VERSION 5.7 ;
BUSBITCHARS "[]" ;
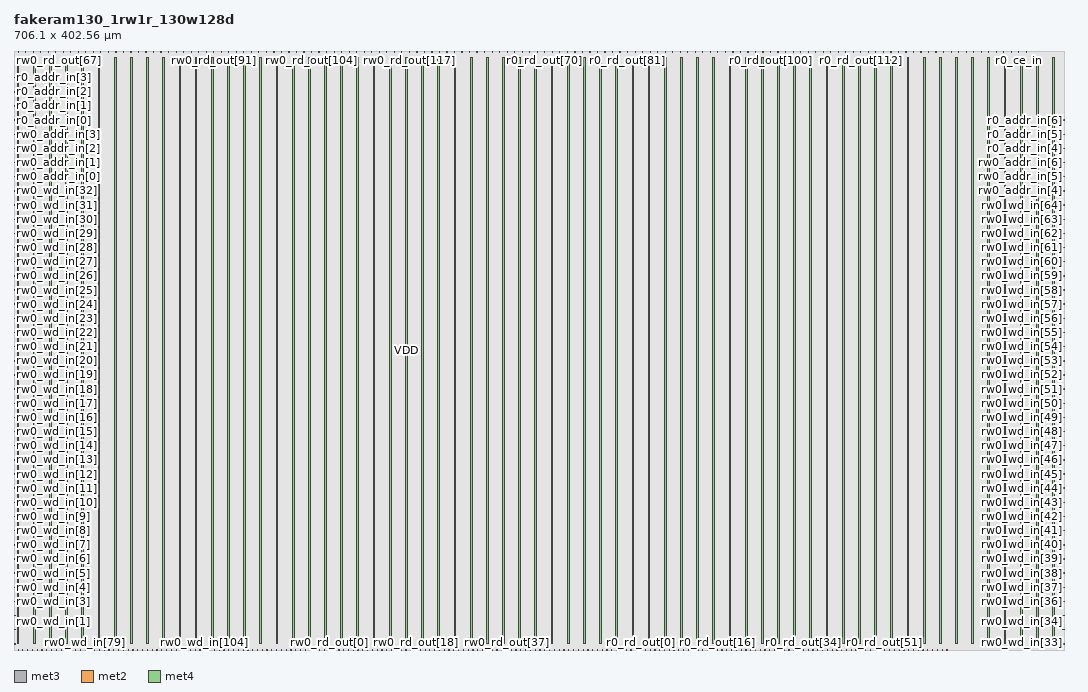
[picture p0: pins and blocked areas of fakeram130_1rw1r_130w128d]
MACRO fakeram130_1rw1r_130w128d
  FOREIGN fakeram130_1rw1r_130w128d 0 0 ;
  SYMMETRY X Y R90 ;
  SIZE 706.100 BY 402.560 ;
  CLASS BLOCK ;
  PIN rw0_wd_in[0]
    DIRECTION INPUT ;
    USE SIGNAL ;
    SHAPE ABUTMENT ;
    PORT
      LAYER met3 ;
      RECT 0.000 3.930 0.900 4.230 ;
    END
  END rw0_wd_in[0]
  PIN rw0_wd_in[1]
    DIRECTION INPUT ;
    USE SIGNAL ;
    SHAPE ABUTMENT ;
    PORT
      LAYER met3 ;
      RECT 0.000 13.450 0.900 13.750 ;
    END
  END rw0_wd_in[1]
  PIN rw0_wd_in[2]
    DIRECTION INPUT ;
    USE SIGNAL ;
    SHAPE ABUTMENT ;
    PORT
      LAYER met3 ;
      RECT 0.000 22.970 0.900 23.270 ;
    END
  END rw0_wd_in[2]
  PIN rw0_wd_in[3]
    DIRECTION INPUT ;
    USE SIGNAL ;
    SHAPE ABUTMENT ;
    PORT
      LAYER met3 ;
      RECT 0.000 32.490 0.900 32.790 ;
    END
  END rw0_wd_in[3]
  PIN rw0_wd_in[4]
    DIRECTION INPUT ;
    USE SIGNAL ;
    SHAPE ABUTMENT ;
    PORT
      LAYER met3 ;
      RECT 0.000 42.010 0.900 42.310 ;
    END
  END rw0_wd_in[4]
  PIN rw0_wd_in[5]
    DIRECTION INPUT ;
    USE SIGNAL ;
    SHAPE ABUTMENT ;
    PORT
      LAYER met3 ;
      RECT 0.000 51.530 0.900 51.830 ;
    END
  END rw0_wd_in[5]
  PIN rw0_wd_in[6]
    DIRECTION INPUT ;
    USE SIGNAL ;
    SHAPE ABUTMENT ;
    PORT
      LAYER met3 ;
      RECT 0.000 61.050 0.900 61.350 ;
    END
  END rw0_wd_in[6]
  PIN rw0_wd_in[7]
    DIRECTION INPUT ;
    USE SIGNAL ;
    SHAPE ABUTMENT ;
    PORT
      LAYER met3 ;
      RECT 0.000 70.570 0.900 70.870 ;
    END
  END rw0_wd_in[7]
  PIN rw0_wd_in[8]
    DIRECTION INPUT ;
    USE SIGNAL ;
    SHAPE ABUTMENT ;
    PORT
      LAYER met3 ;
      RECT 0.000 80.090 0.900 80.390 ;
    END
  END rw0_wd_in[8]
  PIN rw0_wd_in[9]
    DIRECTION INPUT ;
    USE SIGNAL ;
    SHAPE ABUTMENT ;
    PORT
      LAYER met3 ;
      RECT 0.000 89.610 0.900 89.910 ;
    END
  END rw0_wd_in[9]
  PIN rw0_wd_in[10]
    DIRECTION INPUT ;
    USE SIGNAL ;
    SHAPE ABUTMENT ;
    PORT
      LAYER met3 ;
      RECT 0.000 99.130 0.900 99.430 ;
    END
  END rw0_wd_in[10]
  PIN rw0_wd_in[11]
    DIRECTION INPUT ;
    USE SIGNAL ;
    SHAPE ABUTMENT ;
    PORT
      LAYER met3 ;
      RECT 0.000 108.650 0.900 108.950 ;
    END
  END rw0_wd_in[11]
  PIN rw0_wd_in[12]
    DIRECTION INPUT ;
    USE SIGNAL ;
    SHAPE ABUTMENT ;
    PORT
      LAYER met3 ;
      RECT 0.000 118.170 0.900 118.470 ;
    END
  END rw0_wd_in[12]
  PIN rw0_wd_in[13]
    DIRECTION INPUT ;
    USE SIGNAL ;
    SHAPE ABUTMENT ;
    PORT
      LAYER met3 ;
      RECT 0.000 127.690 0.900 127.990 ;
    END
  END rw0_wd_in[13]
  PIN rw0_wd_in[14]
    DIRECTION INPUT ;
    USE SIGNAL ;
    SHAPE ABUTMENT ;
    PORT
      LAYER met3 ;
      RECT 0.000 137.210 0.900 137.510 ;
    END
  END rw0_wd_in[14]
  PIN rw0_wd_in[15]
    DIRECTION INPUT ;
    USE SIGNAL ;
    SHAPE ABUTMENT ;
    PORT
      LAYER met3 ;
      RECT 0.000 146.730 0.900 147.030 ;
    END
  END rw0_wd_in[15]
  PIN rw0_wd_in[16]
    DIRECTION INPUT ;
    USE SIGNAL ;
    SHAPE ABUTMENT ;
    PORT
      LAYER met3 ;
      RECT 0.000 156.250 0.900 156.550 ;
    END
  END rw0_wd_in[16]
  PIN rw0_wd_in[17]
    DIRECTION INPUT ;
    USE SIGNAL ;
    SHAPE ABUTMENT ;
    PORT
      LAYER met3 ;
      RECT 0.000 165.770 0.900 166.070 ;
    END
  END rw0_wd_in[17]
  PIN rw0_wd_in[18]
    DIRECTION INPUT ;
    USE SIGNAL ;
    SHAPE ABUTMENT ;
    PORT
      LAYER met3 ;
      RECT 0.000 175.290 0.900 175.590 ;
    END
  END rw0_wd_in[18]
  PIN rw0_wd_in[19]
    DIRECTION INPUT ;
    USE SIGNAL ;
    SHAPE ABUTMENT ;
    PORT
      LAYER met3 ;
      RECT 0.000 184.810 0.900 185.110 ;
    END
  END rw0_wd_in[19]
  PIN rw0_wd_in[20]
    DIRECTION INPUT ;
    USE SIGNAL ;
    SHAPE ABUTMENT ;
    PORT
      LAYER met3 ;
      RECT 0.000 194.330 0.900 194.630 ;
    END
  END rw0_wd_in[20]
  PIN rw0_wd_in[21]
    DIRECTION INPUT ;
    USE SIGNAL ;
    SHAPE ABUTMENT ;
    PORT
      LAYER met3 ;
      RECT 0.000 203.850 0.900 204.150 ;
    END
  END rw0_wd_in[21]
  PIN rw0_wd_in[22]
    DIRECTION INPUT ;
    USE SIGNAL ;
    SHAPE ABUTMENT ;
    PORT
      LAYER met3 ;
      RECT 0.000 213.370 0.900 213.670 ;
    END
  END rw0_wd_in[22]
  PIN rw0_wd_in[23]
    DIRECTION INPUT ;
    USE SIGNAL ;
    SHAPE ABUTMENT ;
    PORT
      LAYER met3 ;
      RECT 0.000 222.890 0.900 223.190 ;
    END
  END rw0_wd_in[23]
  PIN rw0_wd_in[24]
    DIRECTION INPUT ;
    USE SIGNAL ;
    SHAPE ABUTMENT ;
    PORT
      LAYER met3 ;
      RECT 0.000 232.410 0.900 232.710 ;
    END
  END rw0_wd_in[24]
  PIN rw0_wd_in[25]
    DIRECTION INPUT ;
    USE SIGNAL ;
    SHAPE ABUTMENT ;
    PORT
      LAYER met3 ;
      RECT 0.000 241.930 0.900 242.230 ;
    END
  END rw0_wd_in[25]
  PIN rw0_wd_in[26]
    DIRECTION INPUT ;
    USE SIGNAL ;
    SHAPE ABUTMENT ;
    PORT
      LAYER met3 ;
      RECT 0.000 251.450 0.900 251.750 ;
    END
  END rw0_wd_in[26]
  PIN rw0_wd_in[27]
    DIRECTION INPUT ;
    USE SIGNAL ;
    SHAPE ABUTMENT ;
    PORT
      LAYER met3 ;
      RECT 0.000 260.970 0.900 261.270 ;
    END
  END rw0_wd_in[27]
  PIN rw0_wd_in[28]
    DIRECTION INPUT ;
    USE SIGNAL ;
    SHAPE ABUTMENT ;
    PORT
      LAYER met3 ;
      RECT 0.000 270.490 0.900 270.790 ;
    END
  END rw0_wd_in[28]
  PIN rw0_wd_in[29]
    DIRECTION INPUT ;
    USE SIGNAL ;
    SHAPE ABUTMENT ;
    PORT
      LAYER met3 ;
      RECT 0.000 280.010 0.900 280.310 ;
    END
  END rw0_wd_in[29]
  PIN rw0_wd_in[30]
    DIRECTION INPUT ;
    USE SIGNAL ;
    SHAPE ABUTMENT ;
    PORT
      LAYER met3 ;
      RECT 0.000 289.530 0.900 289.830 ;
    END
  END rw0_wd_in[30]
  PIN rw0_wd_in[31]
    DIRECTION INPUT ;
    USE SIGNAL ;
    SHAPE ABUTMENT ;
    PORT
      LAYER met3 ;
      RECT 0.000 299.050 0.900 299.350 ;
    END
  END rw0_wd_in[31]
  PIN rw0_wd_in[32]
    DIRECTION INPUT ;
    USE SIGNAL ;
    SHAPE ABUTMENT ;
    PORT
      LAYER met3 ;
      RECT 0.000 308.570 0.900 308.870 ;
    END
  END rw0_wd_in[32]
  PIN rw0_wd_in[33]
    DIRECTION INPUT ;
    USE SIGNAL ;
    SHAPE ABUTMENT ;
    PORT
      LAYER met3 ;
      RECT 705.200 3.930 706.100 4.230 ;
    END
  END rw0_wd_in[33]
  PIN rw0_wd_in[34]
    DIRECTION INPUT ;
    USE SIGNAL ;
    SHAPE ABUTMENT ;
    PORT
      LAYER met3 ;
      RECT 705.200 13.450 706.100 13.750 ;
    END
  END rw0_wd_in[34]
  PIN rw0_wd_in[35]
    DIRECTION INPUT ;
    USE SIGNAL ;
    SHAPE ABUTMENT ;
    PORT
      LAYER met3 ;
      RECT 705.200 22.970 706.100 23.270 ;
    END
  END rw0_wd_in[35]
  PIN rw0_wd_in[36]
    DIRECTION INPUT ;
    USE SIGNAL ;
    SHAPE ABUTMENT ;
    PORT
      LAYER met3 ;
      RECT 705.200 32.490 706.100 32.790 ;
    END
  END rw0_wd_in[36]
  PIN rw0_wd_in[37]
    DIRECTION INPUT ;
    USE SIGNAL ;
    SHAPE ABUTMENT ;
    PORT
      LAYER met3 ;
      RECT 705.200 42.010 706.100 42.310 ;
    END
  END rw0_wd_in[37]
  PIN rw0_wd_in[38]
    DIRECTION INPUT ;
    USE SIGNAL ;
    SHAPE ABUTMENT ;
    PORT
      LAYER met3 ;
      RECT 705.200 51.530 706.100 51.830 ;
    END
  END rw0_wd_in[38]
  PIN rw0_wd_in[39]
    DIRECTION INPUT ;
    USE SIGNAL ;
    SHAPE ABUTMENT ;
    PORT
      LAYER met3 ;
      RECT 705.200 61.050 706.100 61.350 ;
    END
  END rw0_wd_in[39]
  PIN rw0_wd_in[40]
    DIRECTION INPUT ;
    USE SIGNAL ;
    SHAPE ABUTMENT ;
    PORT
      LAYER met3 ;
      RECT 705.200 70.570 706.100 70.870 ;
    END
  END rw0_wd_in[40]
  PIN rw0_wd_in[41]
    DIRECTION INPUT ;
    USE SIGNAL ;
    SHAPE ABUTMENT ;
    PORT
      LAYER met3 ;
      RECT 705.200 80.090 706.100 80.390 ;
    END
  END rw0_wd_in[41]
  PIN rw0_wd_in[42]
    DIRECTION INPUT ;
    USE SIGNAL ;
    SHAPE ABUTMENT ;
    PORT
      LAYER met3 ;
      RECT 705.200 89.610 706.100 89.910 ;
    END
  END rw0_wd_in[42]
  PIN rw0_wd_in[43]
    DIRECTION INPUT ;
    USE SIGNAL ;
    SHAPE ABUTMENT ;
    PORT
      LAYER met3 ;
      RECT 705.200 99.130 706.100 99.430 ;
    END
  END rw0_wd_in[43]
  PIN rw0_wd_in[44]
    DIRECTION INPUT ;
    USE SIGNAL ;
    SHAPE ABUTMENT ;
    PORT
      LAYER met3 ;
      RECT 705.200 108.650 706.100 108.950 ;
    END
  END rw0_wd_in[44]
  PIN rw0_wd_in[45]
    DIRECTION INPUT ;
    USE SIGNAL ;
    SHAPE ABUTMENT ;
    PORT
      LAYER met3 ;
      RECT 705.200 118.170 706.100 118.470 ;
    END
  END rw0_wd_in[45]
  PIN rw0_wd_in[46]
    DIRECTION INPUT ;
    USE SIGNAL ;
    SHAPE ABUTMENT ;
    PORT
      LAYER met3 ;
      RECT 705.200 127.690 706.100 127.990 ;
    END
  END rw0_wd_in[46]
  PIN rw0_wd_in[47]
    DIRECTION INPUT ;
    USE SIGNAL ;
    SHAPE ABUTMENT ;
    PORT
      LAYER met3 ;
      RECT 705.200 137.210 706.100 137.510 ;
    END
  END rw0_wd_in[47]
  PIN rw0_wd_in[48]
    DIRECTION INPUT ;
    USE SIGNAL ;
    SHAPE ABUTMENT ;
    PORT
      LAYER met3 ;
      RECT 705.200 146.730 706.100 147.030 ;
    END
  END rw0_wd_in[48]
  PIN rw0_wd_in[49]
    DIRECTION INPUT ;
    USE SIGNAL ;
    SHAPE ABUTMENT ;
    PORT
      LAYER met3 ;
      RECT 705.200 156.250 706.100 156.550 ;
    END
  END rw0_wd_in[49]
  PIN rw0_wd_in[50]
    DIRECTION INPUT ;
    USE SIGNAL ;
    SHAPE ABUTMENT ;
    PORT
      LAYER met3 ;
      RECT 705.200 165.770 706.100 166.070 ;
    END
  END rw0_wd_in[50]
  PIN rw0_wd_in[51]
    DIRECTION INPUT ;
    USE SIGNAL ;
    SHAPE ABUTMENT ;
    PORT
      LAYER met3 ;
      RECT 705.200 175.290 706.100 175.590 ;
    END
  END rw0_wd_in[51]
  PIN rw0_wd_in[52]
    DIRECTION INPUT ;
    USE SIGNAL ;
    SHAPE ABUTMENT ;
    PORT
      LAYER met3 ;
      RECT 705.200 184.810 706.100 185.110 ;
    END
  END rw0_wd_in[52]
  PIN rw0_wd_in[53]
    DIRECTION INPUT ;
    USE SIGNAL ;
    SHAPE ABUTMENT ;
    PORT
      LAYER met3 ;
      RECT 705.200 194.330 706.100 194.630 ;
    END
  END rw0_wd_in[53]
  PIN rw0_wd_in[54]
    DIRECTION INPUT ;
    USE SIGNAL ;
    SHAPE ABUTMENT ;
    PORT
      LAYER met3 ;
      RECT 705.200 203.850 706.100 204.150 ;
    END
  END rw0_wd_in[54]
  PIN rw0_wd_in[55]
    DIRECTION INPUT ;
    USE SIGNAL ;
    SHAPE ABUTMENT ;
    PORT
      LAYER met3 ;
      RECT 705.200 213.370 706.100 213.670 ;
    END
  END rw0_wd_in[55]
  PIN rw0_wd_in[56]
    DIRECTION INPUT ;
    USE SIGNAL ;
    SHAPE ABUTMENT ;
    PORT
      LAYER met3 ;
      RECT 705.200 222.890 706.100 223.190 ;
    END
  END rw0_wd_in[56]
  PIN rw0_wd_in[57]
    DIRECTION INPUT ;
    USE SIGNAL ;
    SHAPE ABUTMENT ;
    PORT
      LAYER met3 ;
      RECT 705.200 232.410 706.100 232.710 ;
    END
  END rw0_wd_in[57]
  PIN rw0_wd_in[58]
    DIRECTION INPUT ;
    USE SIGNAL ;
    SHAPE ABUTMENT ;
    PORT
      LAYER met3 ;
      RECT 705.200 241.930 706.100 242.230 ;
    END
  END rw0_wd_in[58]
  PIN rw0_wd_in[59]
    DIRECTION INPUT ;
    USE SIGNAL ;
    SHAPE ABUTMENT ;
    PORT
      LAYER met3 ;
      RECT 705.200 251.450 706.100 251.750 ;
    END
  END rw0_wd_in[59]
  PIN rw0_wd_in[60]
    DIRECTION INPUT ;
    USE SIGNAL ;
    SHAPE ABUTMENT ;
    PORT
      LAYER met3 ;
      RECT 705.200 260.970 706.100 261.270 ;
    END
  END rw0_wd_in[60]
  PIN rw0_wd_in[61]
    DIRECTION INPUT ;
    USE SIGNAL ;
    SHAPE ABUTMENT ;
    PORT
      LAYER met3 ;
      RECT 705.200 270.490 706.100 270.790 ;
    END
  END rw0_wd_in[61]
  PIN rw0_wd_in[62]
    DIRECTION INPUT ;
    USE SIGNAL ;
    SHAPE ABUTMENT ;
    PORT
      LAYER met3 ;
      RECT 705.200 280.010 706.100 280.310 ;
    END
  END rw0_wd_in[62]
  PIN rw0_wd_in[63]
    DIRECTION INPUT ;
    USE SIGNAL ;
    SHAPE ABUTMENT ;
    PORT
      LAYER met3 ;
      RECT 705.200 289.530 706.100 289.830 ;
    END
  END rw0_wd_in[63]
  PIN rw0_wd_in[64]
    DIRECTION INPUT ;
    USE SIGNAL ;
    SHAPE ABUTMENT ;
    PORT
      LAYER met3 ;
      RECT 705.200 299.050 706.100 299.350 ;
    END
  END rw0_wd_in[64]
  PIN rw0_wd_in[65]
    DIRECTION OUTPUT ;
    USE SIGNAL ;
    SHAPE ABUTMENT ;
    PORT
      LAYER met2 ;
      RECT 2.690 0.000 2.830 0.420 ;
    END
  END rw0_wd_in[65]
  PIN rw0_wd_in[66]
    DIRECTION OUTPUT ;
    USE SIGNAL ;
    SHAPE ABUTMENT ;
    PORT
      LAYER met2 ;
      RECT 5.910 0.000 6.050 0.420 ;
    END
  END rw0_wd_in[66]
  PIN rw0_wd_in[67]
    DIRECTION OUTPUT ;
    USE SIGNAL ;
    SHAPE ABUTMENT ;
    PORT
      LAYER met2 ;
      RECT 9.130 0.000 9.270 0.420 ;
    END
  END rw0_wd_in[67]
  PIN rw0_wd_in[68]
    DIRECTION OUTPUT ;
    USE SIGNAL ;
    SHAPE ABUTMENT ;
    PORT
      LAYER met2 ;
      RECT 12.350 0.000 12.490 0.420 ;
    END
  END rw0_wd_in[68]
  PIN rw0_wd_in[69]
    DIRECTION OUTPUT ;
    USE SIGNAL ;
    SHAPE ABUTMENT ;
    PORT
      LAYER met2 ;
      RECT 15.570 0.000 15.710 0.420 ;
    END
  END rw0_wd_in[69]
  PIN rw0_wd_in[70]
    DIRECTION OUTPUT ;
    USE SIGNAL ;
    SHAPE ABUTMENT ;
    PORT
      LAYER met2 ;
      RECT 18.790 0.000 18.930 0.420 ;
    END
  END rw0_wd_in[70]
  PIN rw0_wd_in[71]
    DIRECTION OUTPUT ;
    USE SIGNAL ;
    SHAPE ABUTMENT ;
    PORT
      LAYER met2 ;
      RECT 22.010 0.000 22.150 0.420 ;
    END
  END rw0_wd_in[71]
  PIN rw0_wd_in[72]
    DIRECTION OUTPUT ;
    USE SIGNAL ;
    SHAPE ABUTMENT ;
    PORT
      LAYER met2 ;
      RECT 25.230 0.000 25.370 0.420 ;
    END
  END rw0_wd_in[72]
  PIN rw0_wd_in[73]
    DIRECTION OUTPUT ;
    USE SIGNAL ;
    SHAPE ABUTMENT ;
    PORT
      LAYER met2 ;
      RECT 28.450 0.000 28.590 0.420 ;
    END
  END rw0_wd_in[73]
  PIN rw0_wd_in[74]
    DIRECTION OUTPUT ;
    USE SIGNAL ;
    SHAPE ABUTMENT ;
    PORT
      LAYER met2 ;
      RECT 31.670 0.000 31.810 0.420 ;
    END
  END rw0_wd_in[74]
  PIN rw0_wd_in[75]
    DIRECTION OUTPUT ;
    USE SIGNAL ;
    SHAPE ABUTMENT ;
    PORT
      LAYER met2 ;
      RECT 34.890 0.000 35.030 0.420 ;
    END
  END rw0_wd_in[75]
  PIN rw0_wd_in[76]
    DIRECTION OUTPUT ;
    USE SIGNAL ;
    SHAPE ABUTMENT ;
    PORT
      LAYER met2 ;
      RECT 38.110 0.000 38.250 0.420 ;
    END
  END rw0_wd_in[76]
  PIN rw0_wd_in[77]
    DIRECTION OUTPUT ;
    USE SIGNAL ;
    SHAPE ABUTMENT ;
    PORT
      LAYER met2 ;
      RECT 41.330 0.000 41.470 0.420 ;
    END
  END rw0_wd_in[77]
  PIN rw0_wd_in[78]
    DIRECTION OUTPUT ;
    USE SIGNAL ;
    SHAPE ABUTMENT ;
    PORT
      LAYER met2 ;
      RECT 44.550 0.000 44.690 0.420 ;
    END
  END rw0_wd_in[78]
  PIN rw0_wd_in[79]
    DIRECTION OUTPUT ;
    USE SIGNAL ;
    SHAPE ABUTMENT ;
    PORT
      LAYER met2 ;
      RECT 47.770 0.000 47.910 0.420 ;
    END
  END rw0_wd_in[79]
  PIN rw0_wd_in[80]
    DIRECTION OUTPUT ;
    USE SIGNAL ;
    SHAPE ABUTMENT ;
    PORT
      LAYER met2 ;
      RECT 50.990 0.000 51.130 0.420 ;
    END
  END rw0_wd_in[80]
  PIN rw0_wd_in[81]
    DIRECTION OUTPUT ;
    USE SIGNAL ;
    SHAPE ABUTMENT ;
    PORT
      LAYER met2 ;
      RECT 54.210 0.000 54.350 0.420 ;
    END
  END rw0_wd_in[81]
  PIN rw0_wd_in[82]
    DIRECTION OUTPUT ;
    USE SIGNAL ;
    SHAPE ABUTMENT ;
    PORT
      LAYER met2 ;
      RECT 57.430 0.000 57.570 0.420 ;
    END
  END rw0_wd_in[82]
  PIN rw0_wd_in[83]
    DIRECTION OUTPUT ;
    USE SIGNAL ;
    SHAPE ABUTMENT ;
    PORT
      LAYER met2 ;
      RECT 60.650 0.000 60.790 0.420 ;
    END
  END rw0_wd_in[83]
  PIN rw0_wd_in[84]
    DIRECTION OUTPUT ;
    USE SIGNAL ;
    SHAPE ABUTMENT ;
    PORT
      LAYER met2 ;
      RECT 63.870 0.000 64.010 0.420 ;
    END
  END rw0_wd_in[84]
  PIN rw0_wd_in[85]
    DIRECTION OUTPUT ;
    USE SIGNAL ;
    SHAPE ABUTMENT ;
    PORT
      LAYER met2 ;
      RECT 67.090 0.000 67.230 0.420 ;
    END
  END rw0_wd_in[85]
  PIN rw0_wd_in[86]
    DIRECTION OUTPUT ;
    USE SIGNAL ;
    SHAPE ABUTMENT ;
    PORT
      LAYER met2 ;
      RECT 70.310 0.000 70.450 0.420 ;
    END
  END rw0_wd_in[86]
  PIN rw0_wd_in[87]
    DIRECTION OUTPUT ;
    USE SIGNAL ;
    SHAPE ABUTMENT ;
    PORT
      LAYER met2 ;
      RECT 73.530 0.000 73.670 0.420 ;
    END
  END rw0_wd_in[87]
  PIN rw0_wd_in[88]
    DIRECTION OUTPUT ;
    USE SIGNAL ;
    SHAPE ABUTMENT ;
    PORT
      LAYER met2 ;
      RECT 76.750 0.000 76.890 0.420 ;
    END
  END rw0_wd_in[88]
  PIN rw0_wd_in[89]
    DIRECTION OUTPUT ;
    USE SIGNAL ;
    SHAPE ABUTMENT ;
    PORT
      LAYER met2 ;
      RECT 79.970 0.000 80.110 0.420 ;
    END
  END rw0_wd_in[89]
  PIN rw0_wd_in[90]
    DIRECTION OUTPUT ;
    USE SIGNAL ;
    SHAPE ABUTMENT ;
    PORT
      LAYER met2 ;
      RECT 83.190 0.000 83.330 0.420 ;
    END
  END rw0_wd_in[90]
  PIN rw0_wd_in[91]
    DIRECTION OUTPUT ;
    USE SIGNAL ;
    SHAPE ABUTMENT ;
    PORT
      LAYER met2 ;
      RECT 86.410 0.000 86.550 0.420 ;
    END
  END rw0_wd_in[91]
  PIN rw0_wd_in[92]
    DIRECTION OUTPUT ;
    USE SIGNAL ;
    SHAPE ABUTMENT ;
    PORT
      LAYER met2 ;
      RECT 89.630 0.000 89.770 0.420 ;
    END
  END rw0_wd_in[92]
  PIN rw0_wd_in[93]
    DIRECTION OUTPUT ;
    USE SIGNAL ;
    SHAPE ABUTMENT ;
    PORT
      LAYER met2 ;
      RECT 92.850 0.000 92.990 0.420 ;
    END
  END rw0_wd_in[93]
  PIN rw0_wd_in[94]
    DIRECTION OUTPUT ;
    USE SIGNAL ;
    SHAPE ABUTMENT ;
    PORT
      LAYER met2 ;
      RECT 96.070 0.000 96.210 0.420 ;
    END
  END rw0_wd_in[94]
  PIN rw0_wd_in[95]
    DIRECTION OUTPUT ;
    USE SIGNAL ;
    SHAPE ABUTMENT ;
    PORT
      LAYER met2 ;
      RECT 99.290 0.000 99.430 0.420 ;
    END
  END rw0_wd_in[95]
  PIN rw0_wd_in[96]
    DIRECTION OUTPUT ;
    USE SIGNAL ;
    SHAPE ABUTMENT ;
    PORT
      LAYER met2 ;
      RECT 102.510 0.000 102.650 0.420 ;
    END
  END rw0_wd_in[96]
  PIN rw0_wd_in[97]
    DIRECTION OUTPUT ;
    USE SIGNAL ;
    SHAPE ABUTMENT ;
    PORT
      LAYER met2 ;
      RECT 105.730 0.000 105.870 0.420 ;
    END
  END rw0_wd_in[97]
  PIN rw0_wd_in[98]
    DIRECTION OUTPUT ;
    USE SIGNAL ;
    SHAPE ABUTMENT ;
    PORT
      LAYER met2 ;
      RECT 108.950 0.000 109.090 0.420 ;
    END
  END rw0_wd_in[98]
  PIN rw0_wd_in[99]
    DIRECTION OUTPUT ;
    USE SIGNAL ;
    SHAPE ABUTMENT ;
    PORT
      LAYER met2 ;
      RECT 112.170 0.000 112.310 0.420 ;
    END
  END rw0_wd_in[99]
  PIN rw0_wd_in[100]
    DIRECTION OUTPUT ;
    USE SIGNAL ;
    SHAPE ABUTMENT ;
    PORT
      LAYER met2 ;
      RECT 115.390 0.000 115.530 0.420 ;
    END
  END rw0_wd_in[100]
  PIN rw0_wd_in[101]
    DIRECTION OUTPUT ;
    USE SIGNAL ;
    SHAPE ABUTMENT ;
    PORT
      LAYER met2 ;
      RECT 118.610 0.000 118.750 0.420 ;
    END
  END rw0_wd_in[101]
  PIN rw0_wd_in[102]
    DIRECTION OUTPUT ;
    USE SIGNAL ;
    SHAPE ABUTMENT ;
    PORT
      LAYER met2 ;
      RECT 121.830 0.000 121.970 0.420 ;
    END
  END rw0_wd_in[102]
  PIN rw0_wd_in[103]
    DIRECTION OUTPUT ;
    USE SIGNAL ;
    SHAPE ABUTMENT ;
    PORT
      LAYER met2 ;
      RECT 125.050 0.000 125.190 0.420 ;
    END
  END rw0_wd_in[103]
  PIN rw0_wd_in[104]
    DIRECTION OUTPUT ;
    USE SIGNAL ;
    SHAPE ABUTMENT ;
    PORT
      LAYER met2 ;
      RECT 128.270 0.000 128.410 0.420 ;
    END
  END rw0_wd_in[104]
  PIN rw0_wd_in[105]
    DIRECTION OUTPUT ;
    USE SIGNAL ;
    SHAPE ABUTMENT ;
    PORT
      LAYER met2 ;
      RECT 131.490 0.000 131.630 0.420 ;
    END
  END rw0_wd_in[105]
  PIN rw0_wd_in[106]
    DIRECTION OUTPUT ;
    USE SIGNAL ;
    SHAPE ABUTMENT ;
    PORT
      LAYER met2 ;
      RECT 134.710 0.000 134.850 0.420 ;
    END
  END rw0_wd_in[106]
  PIN rw0_wd_in[107]
    DIRECTION OUTPUT ;
    USE SIGNAL ;
    SHAPE ABUTMENT ;
    PORT
      LAYER met2 ;
      RECT 137.930 0.000 138.070 0.420 ;
    END
  END rw0_wd_in[107]
  PIN rw0_wd_in[108]
    DIRECTION OUTPUT ;
    USE SIGNAL ;
    SHAPE ABUTMENT ;
    PORT
      LAYER met2 ;
      RECT 141.150 0.000 141.290 0.420 ;
    END
  END rw0_wd_in[108]
  PIN rw0_wd_in[109]
    DIRECTION OUTPUT ;
    USE SIGNAL ;
    SHAPE ABUTMENT ;
    PORT
      LAYER met2 ;
      RECT 144.370 0.000 144.510 0.420 ;
    END
  END rw0_wd_in[109]
  PIN rw0_wd_in[110]
    DIRECTION OUTPUT ;
    USE SIGNAL ;
    SHAPE ABUTMENT ;
    PORT
      LAYER met2 ;
      RECT 147.590 0.000 147.730 0.420 ;
    END
  END rw0_wd_in[110]
  PIN rw0_wd_in[111]
    DIRECTION OUTPUT ;
    USE SIGNAL ;
    SHAPE ABUTMENT ;
    PORT
      LAYER met2 ;
      RECT 150.810 0.000 150.950 0.420 ;
    END
  END rw0_wd_in[111]
  PIN rw0_wd_in[112]
    DIRECTION OUTPUT ;
    USE SIGNAL ;
    SHAPE ABUTMENT ;
    PORT
      LAYER met2 ;
      RECT 154.030 0.000 154.170 0.420 ;
    END
  END rw0_wd_in[112]
  PIN rw0_wd_in[113]
    DIRECTION OUTPUT ;
    USE SIGNAL ;
    SHAPE ABUTMENT ;
    PORT
      LAYER met2 ;
      RECT 157.250 0.000 157.390 0.420 ;
    END
  END rw0_wd_in[113]
  PIN rw0_wd_in[114]
    DIRECTION OUTPUT ;
    USE SIGNAL ;
    SHAPE ABUTMENT ;
    PORT
      LAYER met2 ;
      RECT 160.470 0.000 160.610 0.420 ;
    END
  END rw0_wd_in[114]
  PIN rw0_wd_in[115]
    DIRECTION OUTPUT ;
    USE SIGNAL ;
    SHAPE ABUTMENT ;
    PORT
      LAYER met2 ;
      RECT 163.690 0.000 163.830 0.420 ;
    END
  END rw0_wd_in[115]
  PIN rw0_wd_in[116]
    DIRECTION OUTPUT ;
    USE SIGNAL ;
    SHAPE ABUTMENT ;
    PORT
      LAYER met2 ;
      RECT 166.910 0.000 167.050 0.420 ;
    END
  END rw0_wd_in[116]
  PIN rw0_wd_in[117]
    DIRECTION OUTPUT ;
    USE SIGNAL ;
    SHAPE ABUTMENT ;
    PORT
      LAYER met2 ;
      RECT 170.130 0.000 170.270 0.420 ;
    END
  END rw0_wd_in[117]
  PIN rw0_wd_in[118]
    DIRECTION OUTPUT ;
    USE SIGNAL ;
    SHAPE ABUTMENT ;
    PORT
      LAYER met2 ;
      RECT 173.350 0.000 173.490 0.420 ;
    END
  END rw0_wd_in[118]
  PIN rw0_wd_in[119]
    DIRECTION OUTPUT ;
    USE SIGNAL ;
    SHAPE ABUTMENT ;
    PORT
      LAYER met2 ;
      RECT 176.570 0.000 176.710 0.420 ;
    END
  END rw0_wd_in[119]
  PIN rw0_wd_in[120]
    DIRECTION OUTPUT ;
    USE SIGNAL ;
    SHAPE ABUTMENT ;
    PORT
      LAYER met2 ;
      RECT 179.790 0.000 179.930 0.420 ;
    END
  END rw0_wd_in[120]
  PIN rw0_wd_in[121]
    DIRECTION OUTPUT ;
    USE SIGNAL ;
    SHAPE ABUTMENT ;
    PORT
      LAYER met2 ;
      RECT 183.010 0.000 183.150 0.420 ;
    END
  END rw0_wd_in[121]
  PIN rw0_wd_in[122]
    DIRECTION OUTPUT ;
    USE SIGNAL ;
    SHAPE ABUTMENT ;
    PORT
      LAYER met2 ;
      RECT 186.230 0.000 186.370 0.420 ;
    END
  END rw0_wd_in[122]
  PIN rw0_wd_in[123]
    DIRECTION OUTPUT ;
    USE SIGNAL ;
    SHAPE ABUTMENT ;
    PORT
      LAYER met2 ;
      RECT 189.450 0.000 189.590 0.420 ;
    END
  END rw0_wd_in[123]
  PIN rw0_wd_in[124]
    DIRECTION OUTPUT ;
    USE SIGNAL ;
    SHAPE ABUTMENT ;
    PORT
      LAYER met2 ;
      RECT 192.670 0.000 192.810 0.420 ;
    END
  END rw0_wd_in[124]
  PIN rw0_wd_in[125]
    DIRECTION OUTPUT ;
    USE SIGNAL ;
    SHAPE ABUTMENT ;
    PORT
      LAYER met2 ;
      RECT 195.890 0.000 196.030 0.420 ;
    END
  END rw0_wd_in[125]
  PIN rw0_wd_in[126]
    DIRECTION OUTPUT ;
    USE SIGNAL ;
    SHAPE ABUTMENT ;
    PORT
      LAYER met2 ;
      RECT 199.110 0.000 199.250 0.420 ;
    END
  END rw0_wd_in[126]
  PIN rw0_wd_in[127]
    DIRECTION OUTPUT ;
    USE SIGNAL ;
    SHAPE ABUTMENT ;
    PORT
      LAYER met2 ;
      RECT 202.330 0.000 202.470 0.420 ;
    END
  END rw0_wd_in[127]
  PIN rw0_wd_in[128]
    DIRECTION OUTPUT ;
    USE SIGNAL ;
    SHAPE ABUTMENT ;
    PORT
      LAYER met2 ;
      RECT 205.550 0.000 205.690 0.420 ;
    END
  END rw0_wd_in[128]
  PIN rw0_wd_in[129]
    DIRECTION OUTPUT ;
    USE SIGNAL ;
    SHAPE ABUTMENT ;
    PORT
      LAYER met2 ;
      RECT 208.770 0.000 208.910 0.420 ;
    END
  END rw0_wd_in[129]
  PIN rw0_rd_out[0]
    DIRECTION OUTPUT ;
    USE SIGNAL ;
    SHAPE ABUTMENT ;
    PORT
      LAYER met2 ;
      RECT 211.990 0.000 212.130 0.420 ;
    END
  END rw0_rd_out[0]
  PIN rw0_rd_out[1]
    DIRECTION OUTPUT ;
    USE SIGNAL ;
    SHAPE ABUTMENT ;
    PORT
      LAYER met2 ;
      RECT 215.210 0.000 215.350 0.420 ;
    END
  END rw0_rd_out[1]
  PIN rw0_rd_out[2]
    DIRECTION OUTPUT ;
    USE SIGNAL ;
    SHAPE ABUTMENT ;
    PORT
      LAYER met2 ;
      RECT 218.430 0.000 218.570 0.420 ;
    END
  END rw0_rd_out[2]
  PIN rw0_rd_out[3]
    DIRECTION OUTPUT ;
    USE SIGNAL ;
    SHAPE ABUTMENT ;
    PORT
      LAYER met2 ;
      RECT 221.650 0.000 221.790 0.420 ;
    END
  END rw0_rd_out[3]
  PIN rw0_rd_out[4]
    DIRECTION OUTPUT ;
    USE SIGNAL ;
    SHAPE ABUTMENT ;
    PORT
      LAYER met2 ;
      RECT 224.870 0.000 225.010 0.420 ;
    END
  END rw0_rd_out[4]
  PIN rw0_rd_out[5]
    DIRECTION OUTPUT ;
    USE SIGNAL ;
    SHAPE ABUTMENT ;
    PORT
      LAYER met2 ;
      RECT 228.090 0.000 228.230 0.420 ;
    END
  END rw0_rd_out[5]
  PIN rw0_rd_out[6]
    DIRECTION OUTPUT ;
    USE SIGNAL ;
    SHAPE ABUTMENT ;
    PORT
      LAYER met2 ;
      RECT 231.310 0.000 231.450 0.420 ;
    END
  END rw0_rd_out[6]
  PIN rw0_rd_out[7]
    DIRECTION OUTPUT ;
    USE SIGNAL ;
    SHAPE ABUTMENT ;
    PORT
      LAYER met2 ;
      RECT 234.530 0.000 234.670 0.420 ;
    END
  END rw0_rd_out[7]
  PIN rw0_rd_out[8]
    DIRECTION OUTPUT ;
    USE SIGNAL ;
    SHAPE ABUTMENT ;
    PORT
      LAYER met2 ;
      RECT 237.750 0.000 237.890 0.420 ;
    END
  END rw0_rd_out[8]
  PIN rw0_rd_out[9]
    DIRECTION OUTPUT ;
    USE SIGNAL ;
    SHAPE ABUTMENT ;
    PORT
      LAYER met2 ;
      RECT 240.970 0.000 241.110 0.420 ;
    END
  END rw0_rd_out[9]
  PIN rw0_rd_out[10]
    DIRECTION OUTPUT ;
    USE SIGNAL ;
    SHAPE ABUTMENT ;
    PORT
      LAYER met2 ;
      RECT 244.190 0.000 244.330 0.420 ;
    END
  END rw0_rd_out[10]
  PIN rw0_rd_out[11]
    DIRECTION OUTPUT ;
    USE SIGNAL ;
    SHAPE ABUTMENT ;
    PORT
      LAYER met2 ;
      RECT 247.410 0.000 247.550 0.420 ;
    END
  END rw0_rd_out[11]
  PIN rw0_rd_out[12]
    DIRECTION OUTPUT ;
    USE SIGNAL ;
    SHAPE ABUTMENT ;
    PORT
      LAYER met2 ;
      RECT 250.630 0.000 250.770 0.420 ;
    END
  END rw0_rd_out[12]
  PIN rw0_rd_out[13]
    DIRECTION OUTPUT ;
    USE SIGNAL ;
    SHAPE ABUTMENT ;
    PORT
      LAYER met2 ;
      RECT 253.850 0.000 253.990 0.420 ;
    END
  END rw0_rd_out[13]
  PIN rw0_rd_out[14]
    DIRECTION OUTPUT ;
    USE SIGNAL ;
    SHAPE ABUTMENT ;
    PORT
      LAYER met2 ;
      RECT 257.070 0.000 257.210 0.420 ;
    END
  END rw0_rd_out[14]
  PIN rw0_rd_out[15]
    DIRECTION OUTPUT ;
    USE SIGNAL ;
    SHAPE ABUTMENT ;
    PORT
      LAYER met2 ;
      RECT 260.290 0.000 260.430 0.420 ;
    END
  END rw0_rd_out[15]
  PIN rw0_rd_out[16]
    DIRECTION OUTPUT ;
    USE SIGNAL ;
    SHAPE ABUTMENT ;
    PORT
      LAYER met2 ;
      RECT 263.510 0.000 263.650 0.420 ;
    END
  END rw0_rd_out[16]
  PIN rw0_rd_out[17]
    DIRECTION OUTPUT ;
    USE SIGNAL ;
    SHAPE ABUTMENT ;
    PORT
      LAYER met2 ;
      RECT 266.730 0.000 266.870 0.420 ;
    END
  END rw0_rd_out[17]
  PIN rw0_rd_out[18]
    DIRECTION OUTPUT ;
    USE SIGNAL ;
    SHAPE ABUTMENT ;
    PORT
      LAYER met2 ;
      RECT 269.950 0.000 270.090 0.420 ;
    END
  END rw0_rd_out[18]
  PIN rw0_rd_out[19]
    DIRECTION OUTPUT ;
    USE SIGNAL ;
    SHAPE ABUTMENT ;
    PORT
      LAYER met2 ;
      RECT 273.170 0.000 273.310 0.420 ;
    END
  END rw0_rd_out[19]
  PIN rw0_rd_out[20]
    DIRECTION OUTPUT ;
    USE SIGNAL ;
    SHAPE ABUTMENT ;
    PORT
      LAYER met2 ;
      RECT 276.390 0.000 276.530 0.420 ;
    END
  END rw0_rd_out[20]
  PIN rw0_rd_out[21]
    DIRECTION OUTPUT ;
    USE SIGNAL ;
    SHAPE ABUTMENT ;
    PORT
      LAYER met2 ;
      RECT 279.610 0.000 279.750 0.420 ;
    END
  END rw0_rd_out[21]
  PIN rw0_rd_out[22]
    DIRECTION OUTPUT ;
    USE SIGNAL ;
    SHAPE ABUTMENT ;
    PORT
      LAYER met2 ;
      RECT 282.830 0.000 282.970 0.420 ;
    END
  END rw0_rd_out[22]
  PIN rw0_rd_out[23]
    DIRECTION OUTPUT ;
    USE SIGNAL ;
    SHAPE ABUTMENT ;
    PORT
      LAYER met2 ;
      RECT 286.050 0.000 286.190 0.420 ;
    END
  END rw0_rd_out[23]
  PIN rw0_rd_out[24]
    DIRECTION OUTPUT ;
    USE SIGNAL ;
    SHAPE ABUTMENT ;
    PORT
      LAYER met2 ;
      RECT 289.270 0.000 289.410 0.420 ;
    END
  END rw0_rd_out[24]
  PIN rw0_rd_out[25]
    DIRECTION OUTPUT ;
    USE SIGNAL ;
    SHAPE ABUTMENT ;
    PORT
      LAYER met2 ;
      RECT 292.490 0.000 292.630 0.420 ;
    END
  END rw0_rd_out[25]
  PIN rw0_rd_out[26]
    DIRECTION OUTPUT ;
    USE SIGNAL ;
    SHAPE ABUTMENT ;
    PORT
      LAYER met2 ;
      RECT 295.710 0.000 295.850 0.420 ;
    END
  END rw0_rd_out[26]
  PIN rw0_rd_out[27]
    DIRECTION OUTPUT ;
    USE SIGNAL ;
    SHAPE ABUTMENT ;
    PORT
      LAYER met2 ;
      RECT 298.930 0.000 299.070 0.420 ;
    END
  END rw0_rd_out[27]
  PIN rw0_rd_out[28]
    DIRECTION OUTPUT ;
    USE SIGNAL ;
    SHAPE ABUTMENT ;
    PORT
      LAYER met2 ;
      RECT 302.150 0.000 302.290 0.420 ;
    END
  END rw0_rd_out[28]
  PIN rw0_rd_out[29]
    DIRECTION OUTPUT ;
    USE SIGNAL ;
    SHAPE ABUTMENT ;
    PORT
      LAYER met2 ;
      RECT 305.370 0.000 305.510 0.420 ;
    END
  END rw0_rd_out[29]
  PIN rw0_rd_out[30]
    DIRECTION OUTPUT ;
    USE SIGNAL ;
    SHAPE ABUTMENT ;
    PORT
      LAYER met2 ;
      RECT 308.590 0.000 308.730 0.420 ;
    END
  END rw0_rd_out[30]
  PIN rw0_rd_out[31]
    DIRECTION OUTPUT ;
    USE SIGNAL ;
    SHAPE ABUTMENT ;
    PORT
      LAYER met2 ;
      RECT 311.810 0.000 311.950 0.420 ;
    END
  END rw0_rd_out[31]
  PIN rw0_rd_out[32]
    DIRECTION OUTPUT ;
    USE SIGNAL ;
    SHAPE ABUTMENT ;
    PORT
      LAYER met2 ;
      RECT 315.030 0.000 315.170 0.420 ;
    END
  END rw0_rd_out[32]
  PIN rw0_rd_out[33]
    DIRECTION OUTPUT ;
    USE SIGNAL ;
    SHAPE ABUTMENT ;
    PORT
      LAYER met2 ;
      RECT 318.250 0.000 318.390 0.420 ;
    END
  END rw0_rd_out[33]
  PIN rw0_rd_out[34]
    DIRECTION OUTPUT ;
    USE SIGNAL ;
    SHAPE ABUTMENT ;
    PORT
      LAYER met2 ;
      RECT 321.470 0.000 321.610 0.420 ;
    END
  END rw0_rd_out[34]
  PIN rw0_rd_out[35]
    DIRECTION OUTPUT ;
    USE SIGNAL ;
    SHAPE ABUTMENT ;
    PORT
      LAYER met2 ;
      RECT 324.690 0.000 324.830 0.420 ;
    END
  END rw0_rd_out[35]
  PIN rw0_rd_out[36]
    DIRECTION OUTPUT ;
    USE SIGNAL ;
    SHAPE ABUTMENT ;
    PORT
      LAYER met2 ;
      RECT 327.910 0.000 328.050 0.420 ;
    END
  END rw0_rd_out[36]
  PIN rw0_rd_out[37]
    DIRECTION OUTPUT ;
    USE SIGNAL ;
    SHAPE ABUTMENT ;
    PORT
      LAYER met2 ;
      RECT 331.130 0.000 331.270 0.420 ;
    END
  END rw0_rd_out[37]
  PIN rw0_rd_out[38]
    DIRECTION OUTPUT ;
    USE SIGNAL ;
    SHAPE ABUTMENT ;
    PORT
      LAYER met2 ;
      RECT 334.350 0.000 334.490 0.420 ;
    END
  END rw0_rd_out[38]
  PIN rw0_rd_out[39]
    DIRECTION OUTPUT ;
    USE SIGNAL ;
    SHAPE ABUTMENT ;
    PORT
      LAYER met2 ;
      RECT 337.570 0.000 337.710 0.420 ;
    END
  END rw0_rd_out[39]
  PIN rw0_rd_out[40]
    DIRECTION OUTPUT ;
    USE SIGNAL ;
    SHAPE ABUTMENT ;
    PORT
      LAYER met2 ;
      RECT 340.790 0.000 340.930 0.420 ;
    END
  END rw0_rd_out[40]
  PIN rw0_rd_out[41]
    DIRECTION OUTPUT ;
    USE SIGNAL ;
    SHAPE ABUTMENT ;
    PORT
      LAYER met2 ;
      RECT 344.010 0.000 344.150 0.420 ;
    END
  END rw0_rd_out[41]
  PIN rw0_rd_out[42]
    DIRECTION OUTPUT ;
    USE SIGNAL ;
    SHAPE ABUTMENT ;
    PORT
      LAYER met2 ;
      RECT 347.230 0.000 347.370 0.420 ;
    END
  END rw0_rd_out[42]
  PIN rw0_rd_out[43]
    DIRECTION OUTPUT ;
    USE SIGNAL ;
    SHAPE ABUTMENT ;
    PORT
      LAYER met2 ;
      RECT 350.450 0.000 350.590 0.420 ;
    END
  END rw0_rd_out[43]
  PIN rw0_rd_out[44]
    DIRECTION OUTPUT ;
    USE SIGNAL ;
    SHAPE ABUTMENT ;
    PORT
      LAYER met2 ;
      RECT 353.670 0.000 353.810 0.420 ;
    END
  END rw0_rd_out[44]
  PIN rw0_rd_out[45]
    DIRECTION OUTPUT ;
    USE SIGNAL ;
    SHAPE ABUTMENT ;
    PORT
      LAYER met2 ;
      RECT 356.890 0.000 357.030 0.420 ;
    END
  END rw0_rd_out[45]
  PIN rw0_rd_out[46]
    DIRECTION OUTPUT ;
    USE SIGNAL ;
    SHAPE ABUTMENT ;
    PORT
      LAYER met2 ;
      RECT 360.110 0.000 360.250 0.420 ;
    END
  END rw0_rd_out[46]
  PIN rw0_rd_out[47]
    DIRECTION OUTPUT ;
    USE SIGNAL ;
    SHAPE ABUTMENT ;
    PORT
      LAYER met2 ;
      RECT 363.330 0.000 363.470 0.420 ;
    END
  END rw0_rd_out[47]
  PIN rw0_rd_out[48]
    DIRECTION OUTPUT ;
    USE SIGNAL ;
    SHAPE ABUTMENT ;
    PORT
      LAYER met2 ;
      RECT 366.550 0.000 366.690 0.420 ;
    END
  END rw0_rd_out[48]
  PIN rw0_rd_out[49]
    DIRECTION OUTPUT ;
    USE SIGNAL ;
    SHAPE ABUTMENT ;
    PORT
      LAYER met2 ;
      RECT 369.770 0.000 369.910 0.420 ;
    END
  END rw0_rd_out[49]
  PIN rw0_rd_out[50]
    DIRECTION OUTPUT ;
    USE SIGNAL ;
    SHAPE ABUTMENT ;
    PORT
      LAYER met2 ;
      RECT 372.990 0.000 373.130 0.420 ;
    END
  END rw0_rd_out[50]
  PIN rw0_rd_out[51]
    DIRECTION OUTPUT ;
    USE SIGNAL ;
    SHAPE ABUTMENT ;
    PORT
      LAYER met2 ;
      RECT 376.210 0.000 376.350 0.420 ;
    END
  END rw0_rd_out[51]
  PIN rw0_rd_out[52]
    DIRECTION OUTPUT ;
    USE SIGNAL ;
    SHAPE ABUTMENT ;
    PORT
      LAYER met2 ;
      RECT 379.430 0.000 379.570 0.420 ;
    END
  END rw0_rd_out[52]
  PIN rw0_rd_out[53]
    DIRECTION OUTPUT ;
    USE SIGNAL ;
    SHAPE ABUTMENT ;
    PORT
      LAYER met2 ;
      RECT 382.650 0.000 382.790 0.420 ;
    END
  END rw0_rd_out[53]
  PIN rw0_rd_out[54]
    DIRECTION OUTPUT ;
    USE SIGNAL ;
    SHAPE ABUTMENT ;
    PORT
      LAYER met2 ;
      RECT 385.870 0.000 386.010 0.420 ;
    END
  END rw0_rd_out[54]
  PIN rw0_rd_out[55]
    DIRECTION OUTPUT ;
    USE SIGNAL ;
    SHAPE ABUTMENT ;
    PORT
      LAYER met2 ;
      RECT 389.090 0.000 389.230 0.420 ;
    END
  END rw0_rd_out[55]
  PIN rw0_rd_out[56]
    DIRECTION OUTPUT ;
    USE SIGNAL ;
    SHAPE ABUTMENT ;
    PORT
      LAYER met2 ;
      RECT 392.310 0.000 392.450 0.420 ;
    END
  END rw0_rd_out[56]
  PIN rw0_rd_out[57]
    DIRECTION OUTPUT ;
    USE SIGNAL ;
    SHAPE ABUTMENT ;
    PORT
      LAYER met2 ;
      RECT 395.530 0.000 395.670 0.420 ;
    END
  END rw0_rd_out[57]
  PIN rw0_rd_out[58]
    DIRECTION OUTPUT ;
    USE SIGNAL ;
    SHAPE ABUTMENT ;
    PORT
      LAYER met2 ;
      RECT 398.750 0.000 398.890 0.420 ;
    END
  END rw0_rd_out[58]
  PIN rw0_rd_out[59]
    DIRECTION OUTPUT ;
    USE SIGNAL ;
    SHAPE ABUTMENT ;
    PORT
      LAYER met2 ;
      RECT 401.970 0.000 402.110 0.420 ;
    END
  END rw0_rd_out[59]
  PIN rw0_rd_out[60]
    DIRECTION OUTPUT ;
    USE SIGNAL ;
    SHAPE ABUTMENT ;
    PORT
      LAYER met2 ;
      RECT 405.190 0.000 405.330 0.420 ;
    END
  END rw0_rd_out[60]
  PIN rw0_rd_out[61]
    DIRECTION OUTPUT ;
    USE SIGNAL ;
    SHAPE ABUTMENT ;
    PORT
      LAYER met2 ;
      RECT 408.410 0.000 408.550 0.420 ;
    END
  END rw0_rd_out[61]
  PIN rw0_rd_out[62]
    DIRECTION OUTPUT ;
    USE SIGNAL ;
    SHAPE ABUTMENT ;
    PORT
      LAYER met2 ;
      RECT 411.630 0.000 411.770 0.420 ;
    END
  END rw0_rd_out[62]
  PIN rw0_rd_out[63]
    DIRECTION OUTPUT ;
    USE SIGNAL ;
    SHAPE ABUTMENT ;
    PORT
      LAYER met2 ;
      RECT 414.850 0.000 414.990 0.420 ;
    END
  END rw0_rd_out[63]
  PIN rw0_rd_out[64]
    DIRECTION OUTPUT ;
    USE SIGNAL ;
    SHAPE ABUTMENT ;
    PORT
      LAYER met2 ;
      RECT 418.070 0.000 418.210 0.420 ;
    END
  END rw0_rd_out[64]
  PIN rw0_rd_out[65]
    DIRECTION OUTPUT ;
    USE SIGNAL ;
    SHAPE ABUTMENT ;
    PORT
      LAYER met2 ;
      RECT 2.690 402.140 2.830 402.560 ;
    END
  END rw0_rd_out[65]
  PIN rw0_rd_out[66]
    DIRECTION OUTPUT ;
    USE SIGNAL ;
    SHAPE ABUTMENT ;
    PORT
      LAYER met2 ;
      RECT 7.750 402.140 7.890 402.560 ;
    END
  END rw0_rd_out[66]
  PIN rw0_rd_out[67]
    DIRECTION OUTPUT ;
    USE SIGNAL ;
    SHAPE ABUTMENT ;
    PORT
      LAYER met2 ;
      RECT 12.810 402.140 12.950 402.560 ;
    END
  END rw0_rd_out[67]
  PIN rw0_rd_out[68]
    DIRECTION OUTPUT ;
    USE SIGNAL ;
    SHAPE ABUTMENT ;
    PORT
      LAYER met2 ;
      RECT 17.870 402.140 18.010 402.560 ;
    END
  END rw0_rd_out[68]
  PIN rw0_rd_out[69]
    DIRECTION OUTPUT ;
    USE SIGNAL ;
    SHAPE ABUTMENT ;
    PORT
      LAYER met2 ;
      RECT 22.930 402.140 23.070 402.560 ;
    END
  END rw0_rd_out[69]
  PIN rw0_rd_out[70]
    DIRECTION OUTPUT ;
    USE SIGNAL ;
    SHAPE ABUTMENT ;
    PORT
      LAYER met2 ;
      RECT 27.990 402.140 28.130 402.560 ;
    END
  END rw0_rd_out[70]
  PIN rw0_rd_out[71]
    DIRECTION OUTPUT ;
    USE SIGNAL ;
    SHAPE ABUTMENT ;
    PORT
      LAYER met2 ;
      RECT 33.050 402.140 33.190 402.560 ;
    END
  END rw0_rd_out[71]
  PIN rw0_rd_out[72]
    DIRECTION OUTPUT ;
    USE SIGNAL ;
    SHAPE ABUTMENT ;
    PORT
      LAYER met2 ;
      RECT 38.110 402.140 38.250 402.560 ;
    END
  END rw0_rd_out[72]
  PIN rw0_rd_out[73]
    DIRECTION OUTPUT ;
    USE SIGNAL ;
    SHAPE ABUTMENT ;
    PORT
      LAYER met2 ;
      RECT 43.170 402.140 43.310 402.560 ;
    END
  END rw0_rd_out[73]
  PIN rw0_rd_out[74]
    DIRECTION OUTPUT ;
    USE SIGNAL ;
    SHAPE ABUTMENT ;
    PORT
      LAYER met2 ;
      RECT 48.230 402.140 48.370 402.560 ;
    END
  END rw0_rd_out[74]
  PIN rw0_rd_out[75]
    DIRECTION OUTPUT ;
    USE SIGNAL ;
    SHAPE ABUTMENT ;
    PORT
      LAYER met2 ;
      RECT 53.290 402.140 53.430 402.560 ;
    END
  END rw0_rd_out[75]
  PIN rw0_rd_out[76]
    DIRECTION OUTPUT ;
    USE SIGNAL ;
    SHAPE ABUTMENT ;
    PORT
      LAYER met2 ;
      RECT 58.350 402.140 58.490 402.560 ;
    END
  END rw0_rd_out[76]
  PIN rw0_rd_out[77]
    DIRECTION OUTPUT ;
    USE SIGNAL ;
    SHAPE ABUTMENT ;
    PORT
      LAYER met2 ;
      RECT 63.410 402.140 63.550 402.560 ;
    END
  END rw0_rd_out[77]
  PIN rw0_rd_out[78]
    DIRECTION OUTPUT ;
    USE SIGNAL ;
    SHAPE ABUTMENT ;
    PORT
      LAYER met2 ;
      RECT 68.470 402.140 68.610 402.560 ;
    END
  END rw0_rd_out[78]
  PIN rw0_rd_out[79]
    DIRECTION OUTPUT ;
    USE SIGNAL ;
    SHAPE ABUTMENT ;
    PORT
      LAYER met2 ;
      RECT 73.530 402.140 73.670 402.560 ;
    END
  END rw0_rd_out[79]
  PIN rw0_rd_out[80]
    DIRECTION OUTPUT ;
    USE SIGNAL ;
    SHAPE ABUTMENT ;
    PORT
      LAYER met2 ;
      RECT 78.590 402.140 78.730 402.560 ;
    END
  END rw0_rd_out[80]
  PIN rw0_rd_out[81]
    DIRECTION OUTPUT ;
    USE SIGNAL ;
    SHAPE ABUTMENT ;
    PORT
      LAYER met2 ;
      RECT 83.650 402.140 83.790 402.560 ;
    END
  END rw0_rd_out[81]
  PIN rw0_rd_out[82]
    DIRECTION OUTPUT ;
    USE SIGNAL ;
    SHAPE ABUTMENT ;
    PORT
      LAYER met2 ;
      RECT 88.710 402.140 88.850 402.560 ;
    END
  END rw0_rd_out[82]
  PIN rw0_rd_out[83]
    DIRECTION OUTPUT ;
    USE SIGNAL ;
    SHAPE ABUTMENT ;
    PORT
      LAYER met2 ;
      RECT 93.770 402.140 93.910 402.560 ;
    END
  END rw0_rd_out[83]
  PIN rw0_rd_out[84]
    DIRECTION OUTPUT ;
    USE SIGNAL ;
    SHAPE ABUTMENT ;
    PORT
      LAYER met2 ;
      RECT 98.830 402.140 98.970 402.560 ;
    END
  END rw0_rd_out[84]
  PIN rw0_rd_out[85]
    DIRECTION OUTPUT ;
    USE SIGNAL ;
    SHAPE ABUTMENT ;
    PORT
      LAYER met2 ;
      RECT 103.890 402.140 104.030 402.560 ;
    END
  END rw0_rd_out[85]
  PIN rw0_rd_out[86]
    DIRECTION OUTPUT ;
    USE SIGNAL ;
    SHAPE ABUTMENT ;
    PORT
      LAYER met2 ;
      RECT 108.950 402.140 109.090 402.560 ;
    END
  END rw0_rd_out[86]
  PIN rw0_rd_out[87]
    DIRECTION OUTPUT ;
    USE SIGNAL ;
    SHAPE ABUTMENT ;
    PORT
      LAYER met2 ;
      RECT 114.010 402.140 114.150 402.560 ;
    END
  END rw0_rd_out[87]
  PIN rw0_rd_out[88]
    DIRECTION OUTPUT ;
    USE SIGNAL ;
    SHAPE ABUTMENT ;
    PORT
      LAYER met2 ;
      RECT 119.070 402.140 119.210 402.560 ;
    END
  END rw0_rd_out[88]
  PIN rw0_rd_out[89]
    DIRECTION OUTPUT ;
    USE SIGNAL ;
    SHAPE ABUTMENT ;
    PORT
      LAYER met2 ;
      RECT 124.130 402.140 124.270 402.560 ;
    END
  END rw0_rd_out[89]
  PIN rw0_rd_out[90]
    DIRECTION OUTPUT ;
    USE SIGNAL ;
    SHAPE ABUTMENT ;
    PORT
      LAYER met2 ;
      RECT 129.190 402.140 129.330 402.560 ;
    END
  END rw0_rd_out[90]
  PIN rw0_rd_out[91]
    DIRECTION OUTPUT ;
    USE SIGNAL ;
    SHAPE ABUTMENT ;
    PORT
      LAYER met2 ;
      RECT 134.250 402.140 134.390 402.560 ;
    END
  END rw0_rd_out[91]
  PIN rw0_rd_out[92]
    DIRECTION OUTPUT ;
    USE SIGNAL ;
    SHAPE ABUTMENT ;
    PORT
      LAYER met2 ;
      RECT 139.310 402.140 139.450 402.560 ;
    END
  END rw0_rd_out[92]
  PIN rw0_rd_out[93]
    DIRECTION OUTPUT ;
    USE SIGNAL ;
    SHAPE ABUTMENT ;
    PORT
      LAYER met2 ;
      RECT 144.370 402.140 144.510 402.560 ;
    END
  END rw0_rd_out[93]
  PIN rw0_rd_out[94]
    DIRECTION OUTPUT ;
    USE SIGNAL ;
    SHAPE ABUTMENT ;
    PORT
      LAYER met2 ;
      RECT 149.430 402.140 149.570 402.560 ;
    END
  END rw0_rd_out[94]
  PIN rw0_rd_out[95]
    DIRECTION OUTPUT ;
    USE SIGNAL ;
    SHAPE ABUTMENT ;
    PORT
      LAYER met2 ;
      RECT 154.490 402.140 154.630 402.560 ;
    END
  END rw0_rd_out[95]
  PIN rw0_rd_out[96]
    DIRECTION OUTPUT ;
    USE SIGNAL ;
    SHAPE ABUTMENT ;
    PORT
      LAYER met2 ;
      RECT 159.550 402.140 159.690 402.560 ;
    END
  END rw0_rd_out[96]
  PIN rw0_rd_out[97]
    DIRECTION OUTPUT ;
    USE SIGNAL ;
    SHAPE ABUTMENT ;
    PORT
      LAYER met2 ;
      RECT 164.610 402.140 164.750 402.560 ;
    END
  END rw0_rd_out[97]
  PIN rw0_rd_out[98]
    DIRECTION OUTPUT ;
    USE SIGNAL ;
    SHAPE ABUTMENT ;
    PORT
      LAYER met2 ;
      RECT 169.670 402.140 169.810 402.560 ;
    END
  END rw0_rd_out[98]
  PIN rw0_rd_out[99]
    DIRECTION OUTPUT ;
    USE SIGNAL ;
    SHAPE ABUTMENT ;
    PORT
      LAYER met2 ;
      RECT 174.730 402.140 174.870 402.560 ;
    END
  END rw0_rd_out[99]
  PIN rw0_rd_out[100]
    DIRECTION OUTPUT ;
    USE SIGNAL ;
    SHAPE ABUTMENT ;
    PORT
      LAYER met2 ;
      RECT 179.790 402.140 179.930 402.560 ;
    END
  END rw0_rd_out[100]
  PIN rw0_rd_out[101]
    DIRECTION OUTPUT ;
    USE SIGNAL ;
    SHAPE ABUTMENT ;
    PORT
      LAYER met2 ;
      RECT 184.850 402.140 184.990 402.560 ;
    END
  END rw0_rd_out[101]
  PIN rw0_rd_out[102]
    DIRECTION OUTPUT ;
    USE SIGNAL ;
    SHAPE ABUTMENT ;
    PORT
      LAYER met2 ;
      RECT 189.910 402.140 190.050 402.560 ;
    END
  END rw0_rd_out[102]
  PIN rw0_rd_out[103]
    DIRECTION OUTPUT ;
    USE SIGNAL ;
    SHAPE ABUTMENT ;
    PORT
      LAYER met2 ;
      RECT 194.970 402.140 195.110 402.560 ;
    END
  END rw0_rd_out[103]
  PIN rw0_rd_out[104]
    DIRECTION OUTPUT ;
    USE SIGNAL ;
    SHAPE ABUTMENT ;
    PORT
      LAYER met2 ;
      RECT 200.030 402.140 200.170 402.560 ;
    END
  END rw0_rd_out[104]
  PIN rw0_rd_out[105]
    DIRECTION OUTPUT ;
    USE SIGNAL ;
    SHAPE ABUTMENT ;
    PORT
      LAYER met2 ;
      RECT 205.090 402.140 205.230 402.560 ;
    END
  END rw0_rd_out[105]
  PIN rw0_rd_out[106]
    DIRECTION OUTPUT ;
    USE SIGNAL ;
    SHAPE ABUTMENT ;
    PORT
      LAYER met2 ;
      RECT 210.150 402.140 210.290 402.560 ;
    END
  END rw0_rd_out[106]
  PIN rw0_rd_out[107]
    DIRECTION OUTPUT ;
    USE SIGNAL ;
    SHAPE ABUTMENT ;
    PORT
      LAYER met2 ;
      RECT 215.210 402.140 215.350 402.560 ;
    END
  END rw0_rd_out[107]
  PIN rw0_rd_out[108]
    DIRECTION OUTPUT ;
    USE SIGNAL ;
    SHAPE ABUTMENT ;
    PORT
      LAYER met2 ;
      RECT 220.270 402.140 220.410 402.560 ;
    END
  END rw0_rd_out[108]
  PIN rw0_rd_out[109]
    DIRECTION OUTPUT ;
    USE SIGNAL ;
    SHAPE ABUTMENT ;
    PORT
      LAYER met2 ;
      RECT 225.330 402.140 225.470 402.560 ;
    END
  END rw0_rd_out[109]
  PIN rw0_rd_out[110]
    DIRECTION OUTPUT ;
    USE SIGNAL ;
    SHAPE ABUTMENT ;
    PORT
      LAYER met2 ;
      RECT 230.390 402.140 230.530 402.560 ;
    END
  END rw0_rd_out[110]
  PIN rw0_rd_out[111]
    DIRECTION OUTPUT ;
    USE SIGNAL ;
    SHAPE ABUTMENT ;
    PORT
      LAYER met2 ;
      RECT 235.450 402.140 235.590 402.560 ;
    END
  END rw0_rd_out[111]
  PIN rw0_rd_out[112]
    DIRECTION OUTPUT ;
    USE SIGNAL ;
    SHAPE ABUTMENT ;
    PORT
      LAYER met2 ;
      RECT 240.510 402.140 240.650 402.560 ;
    END
  END rw0_rd_out[112]
  PIN rw0_rd_out[113]
    DIRECTION OUTPUT ;
    USE SIGNAL ;
    SHAPE ABUTMENT ;
    PORT
      LAYER met2 ;
      RECT 245.570 402.140 245.710 402.560 ;
    END
  END rw0_rd_out[113]
  PIN rw0_rd_out[114]
    DIRECTION OUTPUT ;
    USE SIGNAL ;
    SHAPE ABUTMENT ;
    PORT
      LAYER met2 ;
      RECT 250.630 402.140 250.770 402.560 ;
    END
  END rw0_rd_out[114]
  PIN rw0_rd_out[115]
    DIRECTION OUTPUT ;
    USE SIGNAL ;
    SHAPE ABUTMENT ;
    PORT
      LAYER met2 ;
      RECT 255.690 402.140 255.830 402.560 ;
    END
  END rw0_rd_out[115]
  PIN rw0_rd_out[116]
    DIRECTION OUTPUT ;
    USE SIGNAL ;
    SHAPE ABUTMENT ;
    PORT
      LAYER met2 ;
      RECT 260.750 402.140 260.890 402.560 ;
    END
  END rw0_rd_out[116]
  PIN rw0_rd_out[117]
    DIRECTION OUTPUT ;
    USE SIGNAL ;
    SHAPE ABUTMENT ;
    PORT
      LAYER met2 ;
      RECT 265.810 402.140 265.950 402.560 ;
    END
  END rw0_rd_out[117]
  PIN rw0_rd_out[118]
    DIRECTION OUTPUT ;
    USE SIGNAL ;
    SHAPE ABUTMENT ;
    PORT
      LAYER met2 ;
      RECT 270.870 402.140 271.010 402.560 ;
    END
  END rw0_rd_out[118]
  PIN rw0_rd_out[119]
    DIRECTION OUTPUT ;
    USE SIGNAL ;
    SHAPE ABUTMENT ;
    PORT
      LAYER met2 ;
      RECT 275.930 402.140 276.070 402.560 ;
    END
  END rw0_rd_out[119]
  PIN rw0_rd_out[120]
    DIRECTION OUTPUT ;
    USE SIGNAL ;
    SHAPE ABUTMENT ;
    PORT
      LAYER met2 ;
      RECT 280.990 402.140 281.130 402.560 ;
    END
  END rw0_rd_out[120]
  PIN rw0_rd_out[121]
    DIRECTION OUTPUT ;
    USE SIGNAL ;
    SHAPE ABUTMENT ;
    PORT
      LAYER met2 ;
      RECT 286.050 402.140 286.190 402.560 ;
    END
  END rw0_rd_out[121]
  PIN rw0_rd_out[122]
    DIRECTION OUTPUT ;
    USE SIGNAL ;
    SHAPE ABUTMENT ;
    PORT
      LAYER met2 ;
      RECT 291.110 402.140 291.250 402.560 ;
    END
  END rw0_rd_out[122]
  PIN rw0_rd_out[123]
    DIRECTION OUTPUT ;
    USE SIGNAL ;
    SHAPE ABUTMENT ;
    PORT
      LAYER met2 ;
      RECT 296.170 402.140 296.310 402.560 ;
    END
  END rw0_rd_out[123]
  PIN rw0_rd_out[124]
    DIRECTION OUTPUT ;
    USE SIGNAL ;
    SHAPE ABUTMENT ;
    PORT
      LAYER met2 ;
      RECT 301.230 402.140 301.370 402.560 ;
    END
  END rw0_rd_out[124]
  PIN rw0_rd_out[125]
    DIRECTION OUTPUT ;
    USE SIGNAL ;
    SHAPE ABUTMENT ;
    PORT
      LAYER met2 ;
      RECT 306.290 402.140 306.430 402.560 ;
    END
  END rw0_rd_out[125]
  PIN rw0_rd_out[126]
    DIRECTION OUTPUT ;
    USE SIGNAL ;
    SHAPE ABUTMENT ;
    PORT
      LAYER met2 ;
      RECT 311.350 402.140 311.490 402.560 ;
    END
  END rw0_rd_out[126]
  PIN rw0_rd_out[127]
    DIRECTION OUTPUT ;
    USE SIGNAL ;
    SHAPE ABUTMENT ;
    PORT
      LAYER met2 ;
      RECT 316.410 402.140 316.550 402.560 ;
    END
  END rw0_rd_out[127]
  PIN rw0_rd_out[128]
    DIRECTION OUTPUT ;
    USE SIGNAL ;
    SHAPE ABUTMENT ;
    PORT
      LAYER met2 ;
      RECT 321.470 402.140 321.610 402.560 ;
    END
  END rw0_rd_out[128]
  PIN rw0_rd_out[129]
    DIRECTION OUTPUT ;
    USE SIGNAL ;
    SHAPE ABUTMENT ;
    PORT
      LAYER met2 ;
      RECT 326.530 402.140 326.670 402.560 ;
    END
  END rw0_rd_out[129]
  PIN r0_rd_out[0]
    DIRECTION OUTPUT ;
    USE SIGNAL ;
    SHAPE ABUTMENT ;
    PORT
      LAYER met2 ;
      RECT 421.290 0.000 421.430 0.420 ;
    END
  END r0_rd_out[0]
  PIN r0_rd_out[1]
    DIRECTION OUTPUT ;
    USE SIGNAL ;
    SHAPE ABUTMENT ;
    PORT
      LAYER met2 ;
      RECT 424.510 0.000 424.650 0.420 ;
    END
  END r0_rd_out[1]
  PIN r0_rd_out[2]
    DIRECTION OUTPUT ;
    USE SIGNAL ;
    SHAPE ABUTMENT ;
    PORT
      LAYER met2 ;
      RECT 427.730 0.000 427.870 0.420 ;
    END
  END r0_rd_out[2]
  PIN r0_rd_out[3]
    DIRECTION OUTPUT ;
    USE SIGNAL ;
    SHAPE ABUTMENT ;
    PORT
      LAYER met2 ;
      RECT 430.950 0.000 431.090 0.420 ;
    END
  END r0_rd_out[3]
  PIN r0_rd_out[4]
    DIRECTION OUTPUT ;
    USE SIGNAL ;
    SHAPE ABUTMENT ;
    PORT
      LAYER met2 ;
      RECT 434.170 0.000 434.310 0.420 ;
    END
  END r0_rd_out[4]
  PIN r0_rd_out[5]
    DIRECTION OUTPUT ;
    USE SIGNAL ;
    SHAPE ABUTMENT ;
    PORT
      LAYER met2 ;
      RECT 437.390 0.000 437.530 0.420 ;
    END
  END r0_rd_out[5]
  PIN r0_rd_out[6]
    DIRECTION OUTPUT ;
    USE SIGNAL ;
    SHAPE ABUTMENT ;
    PORT
      LAYER met2 ;
      RECT 440.610 0.000 440.750 0.420 ;
    END
  END r0_rd_out[6]
  PIN r0_rd_out[7]
    DIRECTION OUTPUT ;
    USE SIGNAL ;
    SHAPE ABUTMENT ;
    PORT
      LAYER met2 ;
      RECT 443.830 0.000 443.970 0.420 ;
    END
  END r0_rd_out[7]
  PIN r0_rd_out[8]
    DIRECTION OUTPUT ;
    USE SIGNAL ;
    SHAPE ABUTMENT ;
    PORT
      LAYER met2 ;
      RECT 447.050 0.000 447.190 0.420 ;
    END
  END r0_rd_out[8]
  PIN r0_rd_out[9]
    DIRECTION OUTPUT ;
    USE SIGNAL ;
    SHAPE ABUTMENT ;
    PORT
      LAYER met2 ;
      RECT 450.270 0.000 450.410 0.420 ;
    END
  END r0_rd_out[9]
  PIN r0_rd_out[10]
    DIRECTION OUTPUT ;
    USE SIGNAL ;
    SHAPE ABUTMENT ;
    PORT
      LAYER met2 ;
      RECT 453.490 0.000 453.630 0.420 ;
    END
  END r0_rd_out[10]
  PIN r0_rd_out[11]
    DIRECTION OUTPUT ;
    USE SIGNAL ;
    SHAPE ABUTMENT ;
    PORT
      LAYER met2 ;
      RECT 456.710 0.000 456.850 0.420 ;
    END
  END r0_rd_out[11]
  PIN r0_rd_out[12]
    DIRECTION OUTPUT ;
    USE SIGNAL ;
    SHAPE ABUTMENT ;
    PORT
      LAYER met2 ;
      RECT 459.930 0.000 460.070 0.420 ;
    END
  END r0_rd_out[12]
  PIN r0_rd_out[13]
    DIRECTION OUTPUT ;
    USE SIGNAL ;
    SHAPE ABUTMENT ;
    PORT
      LAYER met2 ;
      RECT 463.150 0.000 463.290 0.420 ;
    END
  END r0_rd_out[13]
  PIN r0_rd_out[14]
    DIRECTION OUTPUT ;
    USE SIGNAL ;
    SHAPE ABUTMENT ;
    PORT
      LAYER met2 ;
      RECT 466.370 0.000 466.510 0.420 ;
    END
  END r0_rd_out[14]
  PIN r0_rd_out[15]
    DIRECTION OUTPUT ;
    USE SIGNAL ;
    SHAPE ABUTMENT ;
    PORT
      LAYER met2 ;
      RECT 469.590 0.000 469.730 0.420 ;
    END
  END r0_rd_out[15]
  PIN r0_rd_out[16]
    DIRECTION OUTPUT ;
    USE SIGNAL ;
    SHAPE ABUTMENT ;
    PORT
      LAYER met2 ;
      RECT 472.810 0.000 472.950 0.420 ;
    END
  END r0_rd_out[16]
  PIN r0_rd_out[17]
    DIRECTION OUTPUT ;
    USE SIGNAL ;
    SHAPE ABUTMENT ;
    PORT
      LAYER met2 ;
      RECT 476.030 0.000 476.170 0.420 ;
    END
  END r0_rd_out[17]
  PIN r0_rd_out[18]
    DIRECTION OUTPUT ;
    USE SIGNAL ;
    SHAPE ABUTMENT ;
    PORT
      LAYER met2 ;
      RECT 479.250 0.000 479.390 0.420 ;
    END
  END r0_rd_out[18]
  PIN r0_rd_out[19]
    DIRECTION OUTPUT ;
    USE SIGNAL ;
    SHAPE ABUTMENT ;
    PORT
      LAYER met2 ;
      RECT 482.470 0.000 482.610 0.420 ;
    END
  END r0_rd_out[19]
  PIN r0_rd_out[20]
    DIRECTION OUTPUT ;
    USE SIGNAL ;
    SHAPE ABUTMENT ;
    PORT
      LAYER met2 ;
      RECT 485.690 0.000 485.830 0.420 ;
    END
  END r0_rd_out[20]
  PIN r0_rd_out[21]
    DIRECTION OUTPUT ;
    USE SIGNAL ;
    SHAPE ABUTMENT ;
    PORT
      LAYER met2 ;
      RECT 488.910 0.000 489.050 0.420 ;
    END
  END r0_rd_out[21]
  PIN r0_rd_out[22]
    DIRECTION OUTPUT ;
    USE SIGNAL ;
    SHAPE ABUTMENT ;
    PORT
      LAYER met2 ;
      RECT 492.130 0.000 492.270 0.420 ;
    END
  END r0_rd_out[22]
  PIN r0_rd_out[23]
    DIRECTION OUTPUT ;
    USE SIGNAL ;
    SHAPE ABUTMENT ;
    PORT
      LAYER met2 ;
      RECT 495.350 0.000 495.490 0.420 ;
    END
  END r0_rd_out[23]
  PIN r0_rd_out[24]
    DIRECTION OUTPUT ;
    USE SIGNAL ;
    SHAPE ABUTMENT ;
    PORT
      LAYER met2 ;
      RECT 498.570 0.000 498.710 0.420 ;
    END
  END r0_rd_out[24]
  PIN r0_rd_out[25]
    DIRECTION OUTPUT ;
    USE SIGNAL ;
    SHAPE ABUTMENT ;
    PORT
      LAYER met2 ;
      RECT 501.790 0.000 501.930 0.420 ;
    END
  END r0_rd_out[25]
  PIN r0_rd_out[26]
    DIRECTION OUTPUT ;
    USE SIGNAL ;
    SHAPE ABUTMENT ;
    PORT
      LAYER met2 ;
      RECT 505.010 0.000 505.150 0.420 ;
    END
  END r0_rd_out[26]
  PIN r0_rd_out[27]
    DIRECTION OUTPUT ;
    USE SIGNAL ;
    SHAPE ABUTMENT ;
    PORT
      LAYER met2 ;
      RECT 508.230 0.000 508.370 0.420 ;
    END
  END r0_rd_out[27]
  PIN r0_rd_out[28]
    DIRECTION OUTPUT ;
    USE SIGNAL ;
    SHAPE ABUTMENT ;
    PORT
      LAYER met2 ;
      RECT 511.450 0.000 511.590 0.420 ;
    END
  END r0_rd_out[28]
  PIN r0_rd_out[29]
    DIRECTION OUTPUT ;
    USE SIGNAL ;
    SHAPE ABUTMENT ;
    PORT
      LAYER met2 ;
      RECT 514.670 0.000 514.810 0.420 ;
    END
  END r0_rd_out[29]
  PIN r0_rd_out[30]
    DIRECTION OUTPUT ;
    USE SIGNAL ;
    SHAPE ABUTMENT ;
    PORT
      LAYER met2 ;
      RECT 517.890 0.000 518.030 0.420 ;
    END
  END r0_rd_out[30]
  PIN r0_rd_out[31]
    DIRECTION OUTPUT ;
    USE SIGNAL ;
    SHAPE ABUTMENT ;
    PORT
      LAYER met2 ;
      RECT 521.110 0.000 521.250 0.420 ;
    END
  END r0_rd_out[31]
  PIN r0_rd_out[32]
    DIRECTION OUTPUT ;
    USE SIGNAL ;
    SHAPE ABUTMENT ;
    PORT
      LAYER met2 ;
      RECT 524.330 0.000 524.470 0.420 ;
    END
  END r0_rd_out[32]
  PIN r0_rd_out[33]
    DIRECTION OUTPUT ;
    USE SIGNAL ;
    SHAPE ABUTMENT ;
    PORT
      LAYER met2 ;
      RECT 527.550 0.000 527.690 0.420 ;
    END
  END r0_rd_out[33]
  PIN r0_rd_out[34]
    DIRECTION OUTPUT ;
    USE SIGNAL ;
    SHAPE ABUTMENT ;
    PORT
      LAYER met2 ;
      RECT 530.770 0.000 530.910 0.420 ;
    END
  END r0_rd_out[34]
  PIN r0_rd_out[35]
    DIRECTION OUTPUT ;
    USE SIGNAL ;
    SHAPE ABUTMENT ;
    PORT
      LAYER met2 ;
      RECT 533.990 0.000 534.130 0.420 ;
    END
  END r0_rd_out[35]
  PIN r0_rd_out[36]
    DIRECTION OUTPUT ;
    USE SIGNAL ;
    SHAPE ABUTMENT ;
    PORT
      LAYER met2 ;
      RECT 537.210 0.000 537.350 0.420 ;
    END
  END r0_rd_out[36]
  PIN r0_rd_out[37]
    DIRECTION OUTPUT ;
    USE SIGNAL ;
    SHAPE ABUTMENT ;
    PORT
      LAYER met2 ;
      RECT 540.430 0.000 540.570 0.420 ;
    END
  END r0_rd_out[37]
  PIN r0_rd_out[38]
    DIRECTION OUTPUT ;
    USE SIGNAL ;
    SHAPE ABUTMENT ;
    PORT
      LAYER met2 ;
      RECT 543.650 0.000 543.790 0.420 ;
    END
  END r0_rd_out[38]
  PIN r0_rd_out[39]
    DIRECTION OUTPUT ;
    USE SIGNAL ;
    SHAPE ABUTMENT ;
    PORT
      LAYER met2 ;
      RECT 546.870 0.000 547.010 0.420 ;
    END
  END r0_rd_out[39]
  PIN r0_rd_out[40]
    DIRECTION OUTPUT ;
    USE SIGNAL ;
    SHAPE ABUTMENT ;
    PORT
      LAYER met2 ;
      RECT 550.090 0.000 550.230 0.420 ;
    END
  END r0_rd_out[40]
  PIN r0_rd_out[41]
    DIRECTION OUTPUT ;
    USE SIGNAL ;
    SHAPE ABUTMENT ;
    PORT
      LAYER met2 ;
      RECT 553.310 0.000 553.450 0.420 ;
    END
  END r0_rd_out[41]
  PIN r0_rd_out[42]
    DIRECTION OUTPUT ;
    USE SIGNAL ;
    SHAPE ABUTMENT ;
    PORT
      LAYER met2 ;
      RECT 556.530 0.000 556.670 0.420 ;
    END
  END r0_rd_out[42]
  PIN r0_rd_out[43]
    DIRECTION OUTPUT ;
    USE SIGNAL ;
    SHAPE ABUTMENT ;
    PORT
      LAYER met2 ;
      RECT 559.750 0.000 559.890 0.420 ;
    END
  END r0_rd_out[43]
  PIN r0_rd_out[44]
    DIRECTION OUTPUT ;
    USE SIGNAL ;
    SHAPE ABUTMENT ;
    PORT
      LAYER met2 ;
      RECT 562.970 0.000 563.110 0.420 ;
    END
  END r0_rd_out[44]
  PIN r0_rd_out[45]
    DIRECTION OUTPUT ;
    USE SIGNAL ;
    SHAPE ABUTMENT ;
    PORT
      LAYER met2 ;
      RECT 566.190 0.000 566.330 0.420 ;
    END
  END r0_rd_out[45]
  PIN r0_rd_out[46]
    DIRECTION OUTPUT ;
    USE SIGNAL ;
    SHAPE ABUTMENT ;
    PORT
      LAYER met2 ;
      RECT 569.410 0.000 569.550 0.420 ;
    END
  END r0_rd_out[46]
  PIN r0_rd_out[47]
    DIRECTION OUTPUT ;
    USE SIGNAL ;
    SHAPE ABUTMENT ;
    PORT
      LAYER met2 ;
      RECT 572.630 0.000 572.770 0.420 ;
    END
  END r0_rd_out[47]
  PIN r0_rd_out[48]
    DIRECTION OUTPUT ;
    USE SIGNAL ;
    SHAPE ABUTMENT ;
    PORT
      LAYER met2 ;
      RECT 575.850 0.000 575.990 0.420 ;
    END
  END r0_rd_out[48]
  PIN r0_rd_out[49]
    DIRECTION OUTPUT ;
    USE SIGNAL ;
    SHAPE ABUTMENT ;
    PORT
      LAYER met2 ;
      RECT 579.070 0.000 579.210 0.420 ;
    END
  END r0_rd_out[49]
  PIN r0_rd_out[50]
    DIRECTION OUTPUT ;
    USE SIGNAL ;
    SHAPE ABUTMENT ;
    PORT
      LAYER met2 ;
      RECT 582.290 0.000 582.430 0.420 ;
    END
  END r0_rd_out[50]
  PIN r0_rd_out[51]
    DIRECTION OUTPUT ;
    USE SIGNAL ;
    SHAPE ABUTMENT ;
    PORT
      LAYER met2 ;
      RECT 585.510 0.000 585.650 0.420 ;
    END
  END r0_rd_out[51]
  PIN r0_rd_out[52]
    DIRECTION OUTPUT ;
    USE SIGNAL ;
    SHAPE ABUTMENT ;
    PORT
      LAYER met2 ;
      RECT 588.730 0.000 588.870 0.420 ;
    END
  END r0_rd_out[52]
  PIN r0_rd_out[53]
    DIRECTION OUTPUT ;
    USE SIGNAL ;
    SHAPE ABUTMENT ;
    PORT
      LAYER met2 ;
      RECT 591.950 0.000 592.090 0.420 ;
    END
  END r0_rd_out[53]
  PIN r0_rd_out[54]
    DIRECTION OUTPUT ;
    USE SIGNAL ;
    SHAPE ABUTMENT ;
    PORT
      LAYER met2 ;
      RECT 595.170 0.000 595.310 0.420 ;
    END
  END r0_rd_out[54]
  PIN r0_rd_out[55]
    DIRECTION OUTPUT ;
    USE SIGNAL ;
    SHAPE ABUTMENT ;
    PORT
      LAYER met2 ;
      RECT 598.390 0.000 598.530 0.420 ;
    END
  END r0_rd_out[55]
  PIN r0_rd_out[56]
    DIRECTION OUTPUT ;
    USE SIGNAL ;
    SHAPE ABUTMENT ;
    PORT
      LAYER met2 ;
      RECT 601.610 0.000 601.750 0.420 ;
    END
  END r0_rd_out[56]
  PIN r0_rd_out[57]
    DIRECTION OUTPUT ;
    USE SIGNAL ;
    SHAPE ABUTMENT ;
    PORT
      LAYER met2 ;
      RECT 604.830 0.000 604.970 0.420 ;
    END
  END r0_rd_out[57]
  PIN r0_rd_out[58]
    DIRECTION OUTPUT ;
    USE SIGNAL ;
    SHAPE ABUTMENT ;
    PORT
      LAYER met2 ;
      RECT 608.050 0.000 608.190 0.420 ;
    END
  END r0_rd_out[58]
  PIN r0_rd_out[59]
    DIRECTION OUTPUT ;
    USE SIGNAL ;
    SHAPE ABUTMENT ;
    PORT
      LAYER met2 ;
      RECT 611.270 0.000 611.410 0.420 ;
    END
  END r0_rd_out[59]
  PIN r0_rd_out[60]
    DIRECTION OUTPUT ;
    USE SIGNAL ;
    SHAPE ABUTMENT ;
    PORT
      LAYER met2 ;
      RECT 614.490 0.000 614.630 0.420 ;
    END
  END r0_rd_out[60]
  PIN r0_rd_out[61]
    DIRECTION OUTPUT ;
    USE SIGNAL ;
    SHAPE ABUTMENT ;
    PORT
      LAYER met2 ;
      RECT 617.710 0.000 617.850 0.420 ;
    END
  END r0_rd_out[61]
  PIN r0_rd_out[62]
    DIRECTION OUTPUT ;
    USE SIGNAL ;
    SHAPE ABUTMENT ;
    PORT
      LAYER met2 ;
      RECT 620.930 0.000 621.070 0.420 ;
    END
  END r0_rd_out[62]
  PIN r0_rd_out[63]
    DIRECTION OUTPUT ;
    USE SIGNAL ;
    SHAPE ABUTMENT ;
    PORT
      LAYER met2 ;
      RECT 624.150 0.000 624.290 0.420 ;
    END
  END r0_rd_out[63]
  PIN r0_rd_out[64]
    DIRECTION OUTPUT ;
    USE SIGNAL ;
    SHAPE ABUTMENT ;
    PORT
      LAYER met2 ;
      RECT 627.370 0.000 627.510 0.420 ;
    END
  END r0_rd_out[64]
  PIN r0_rd_out[65]
    DIRECTION OUTPUT ;
    USE SIGNAL ;
    SHAPE ABUTMENT ;
    PORT
      LAYER met2 ;
      RECT 331.590 402.140 331.730 402.560 ;
    END
  END r0_rd_out[65]
  PIN r0_rd_out[66]
    DIRECTION OUTPUT ;
    USE SIGNAL ;
    SHAPE ABUTMENT ;
    PORT
      LAYER met2 ;
      RECT 336.650 402.140 336.790 402.560 ;
    END
  END r0_rd_out[66]
  PIN r0_rd_out[67]
    DIRECTION OUTPUT ;
    USE SIGNAL ;
    SHAPE ABUTMENT ;
    PORT
      LAYER met2 ;
      RECT 341.710 402.140 341.850 402.560 ;
    END
  END r0_rd_out[67]
  PIN r0_rd_out[68]
    DIRECTION OUTPUT ;
    USE SIGNAL ;
    SHAPE ABUTMENT ;
    PORT
      LAYER met2 ;
      RECT 346.770 402.140 346.910 402.560 ;
    END
  END r0_rd_out[68]
  PIN r0_rd_out[69]
    DIRECTION OUTPUT ;
    USE SIGNAL ;
    SHAPE ABUTMENT ;
    PORT
      LAYER met2 ;
      RECT 351.830 402.140 351.970 402.560 ;
    END
  END r0_rd_out[69]
  PIN r0_rd_out[70]
    DIRECTION OUTPUT ;
    USE SIGNAL ;
    SHAPE ABUTMENT ;
    PORT
      LAYER met2 ;
      RECT 356.890 402.140 357.030 402.560 ;
    END
  END r0_rd_out[70]
  PIN r0_rd_out[71]
    DIRECTION OUTPUT ;
    USE SIGNAL ;
    SHAPE ABUTMENT ;
    PORT
      LAYER met2 ;
      RECT 361.950 402.140 362.090 402.560 ;
    END
  END r0_rd_out[71]
  PIN r0_rd_out[72]
    DIRECTION OUTPUT ;
    USE SIGNAL ;
    SHAPE ABUTMENT ;
    PORT
      LAYER met2 ;
      RECT 367.010 402.140 367.150 402.560 ;
    END
  END r0_rd_out[72]
  PIN r0_rd_out[73]
    DIRECTION OUTPUT ;
    USE SIGNAL ;
    SHAPE ABUTMENT ;
    PORT
      LAYER met2 ;
      RECT 372.070 402.140 372.210 402.560 ;
    END
  END r0_rd_out[73]
  PIN r0_rd_out[74]
    DIRECTION OUTPUT ;
    USE SIGNAL ;
    SHAPE ABUTMENT ;
    PORT
      LAYER met2 ;
      RECT 377.130 402.140 377.270 402.560 ;
    END
  END r0_rd_out[74]
  PIN r0_rd_out[75]
    DIRECTION OUTPUT ;
    USE SIGNAL ;
    SHAPE ABUTMENT ;
    PORT
      LAYER met2 ;
      RECT 382.190 402.140 382.330 402.560 ;
    END
  END r0_rd_out[75]
  PIN r0_rd_out[76]
    DIRECTION OUTPUT ;
    USE SIGNAL ;
    SHAPE ABUTMENT ;
    PORT
      LAYER met2 ;
      RECT 387.250 402.140 387.390 402.560 ;
    END
  END r0_rd_out[76]
  PIN r0_rd_out[77]
    DIRECTION OUTPUT ;
    USE SIGNAL ;
    SHAPE ABUTMENT ;
    PORT
      LAYER met2 ;
      RECT 392.310 402.140 392.450 402.560 ;
    END
  END r0_rd_out[77]
  PIN r0_rd_out[78]
    DIRECTION OUTPUT ;
    USE SIGNAL ;
    SHAPE ABUTMENT ;
    PORT
      LAYER met2 ;
      RECT 397.370 402.140 397.510 402.560 ;
    END
  END r0_rd_out[78]
  PIN r0_rd_out[79]
    DIRECTION OUTPUT ;
    USE SIGNAL ;
    SHAPE ABUTMENT ;
    PORT
      LAYER met2 ;
      RECT 402.430 402.140 402.570 402.560 ;
    END
  END r0_rd_out[79]
  PIN r0_rd_out[80]
    DIRECTION OUTPUT ;
    USE SIGNAL ;
    SHAPE ABUTMENT ;
    PORT
      LAYER met2 ;
      RECT 407.490 402.140 407.630 402.560 ;
    END
  END r0_rd_out[80]
  PIN r0_rd_out[81]
    DIRECTION OUTPUT ;
    USE SIGNAL ;
    SHAPE ABUTMENT ;
    PORT
      LAYER met2 ;
      RECT 412.550 402.140 412.690 402.560 ;
    END
  END r0_rd_out[81]
  PIN r0_rd_out[82]
    DIRECTION OUTPUT ;
    USE SIGNAL ;
    SHAPE ABUTMENT ;
    PORT
      LAYER met2 ;
      RECT 417.610 402.140 417.750 402.560 ;
    END
  END r0_rd_out[82]
  PIN r0_rd_out[83]
    DIRECTION OUTPUT ;
    USE SIGNAL ;
    SHAPE ABUTMENT ;
    PORT
      LAYER met2 ;
      RECT 422.670 402.140 422.810 402.560 ;
    END
  END r0_rd_out[83]
  PIN r0_rd_out[84]
    DIRECTION OUTPUT ;
    USE SIGNAL ;
    SHAPE ABUTMENT ;
    PORT
      LAYER met2 ;
      RECT 427.730 402.140 427.870 402.560 ;
    END
  END r0_rd_out[84]
  PIN r0_rd_out[85]
    DIRECTION OUTPUT ;
    USE SIGNAL ;
    SHAPE ABUTMENT ;
    PORT
      LAYER met2 ;
      RECT 432.790 402.140 432.930 402.560 ;
    END
  END r0_rd_out[85]
  PIN r0_rd_out[86]
    DIRECTION OUTPUT ;
    USE SIGNAL ;
    SHAPE ABUTMENT ;
    PORT
      LAYER met2 ;
      RECT 437.850 402.140 437.990 402.560 ;
    END
  END r0_rd_out[86]
  PIN r0_rd_out[87]
    DIRECTION OUTPUT ;
    USE SIGNAL ;
    SHAPE ABUTMENT ;
    PORT
      LAYER met2 ;
      RECT 442.910 402.140 443.050 402.560 ;
    END
  END r0_rd_out[87]
  PIN r0_rd_out[88]
    DIRECTION OUTPUT ;
    USE SIGNAL ;
    SHAPE ABUTMENT ;
    PORT
      LAYER met2 ;
      RECT 447.970 402.140 448.110 402.560 ;
    END
  END r0_rd_out[88]
  PIN r0_rd_out[89]
    DIRECTION OUTPUT ;
    USE SIGNAL ;
    SHAPE ABUTMENT ;
    PORT
      LAYER met2 ;
      RECT 453.030 402.140 453.170 402.560 ;
    END
  END r0_rd_out[89]
  PIN r0_rd_out[90]
    DIRECTION OUTPUT ;
    USE SIGNAL ;
    SHAPE ABUTMENT ;
    PORT
      LAYER met2 ;
      RECT 458.090 402.140 458.230 402.560 ;
    END
  END r0_rd_out[90]
  PIN r0_rd_out[91]
    DIRECTION OUTPUT ;
    USE SIGNAL ;
    SHAPE ABUTMENT ;
    PORT
      LAYER met2 ;
      RECT 463.150 402.140 463.290 402.560 ;
    END
  END r0_rd_out[91]
  PIN r0_rd_out[92]
    DIRECTION OUTPUT ;
    USE SIGNAL ;
    SHAPE ABUTMENT ;
    PORT
      LAYER met2 ;
      RECT 468.210 402.140 468.350 402.560 ;
    END
  END r0_rd_out[92]
  PIN r0_rd_out[93]
    DIRECTION OUTPUT ;
    USE SIGNAL ;
    SHAPE ABUTMENT ;
    PORT
      LAYER met2 ;
      RECT 473.270 402.140 473.410 402.560 ;
    END
  END r0_rd_out[93]
  PIN r0_rd_out[94]
    DIRECTION OUTPUT ;
    USE SIGNAL ;
    SHAPE ABUTMENT ;
    PORT
      LAYER met2 ;
      RECT 478.330 402.140 478.470 402.560 ;
    END
  END r0_rd_out[94]
  PIN r0_rd_out[95]
    DIRECTION OUTPUT ;
    USE SIGNAL ;
    SHAPE ABUTMENT ;
    PORT
      LAYER met2 ;
      RECT 483.390 402.140 483.530 402.560 ;
    END
  END r0_rd_out[95]
  PIN r0_rd_out[96]
    DIRECTION OUTPUT ;
    USE SIGNAL ;
    SHAPE ABUTMENT ;
    PORT
      LAYER met2 ;
      RECT 488.450 402.140 488.590 402.560 ;
    END
  END r0_rd_out[96]
  PIN r0_rd_out[97]
    DIRECTION OUTPUT ;
    USE SIGNAL ;
    SHAPE ABUTMENT ;
    PORT
      LAYER met2 ;
      RECT 493.510 402.140 493.650 402.560 ;
    END
  END r0_rd_out[97]
  PIN r0_rd_out[98]
    DIRECTION OUTPUT ;
    USE SIGNAL ;
    SHAPE ABUTMENT ;
    PORT
      LAYER met2 ;
      RECT 498.570 402.140 498.710 402.560 ;
    END
  END r0_rd_out[98]
  PIN r0_rd_out[99]
    DIRECTION OUTPUT ;
    USE SIGNAL ;
    SHAPE ABUTMENT ;
    PORT
      LAYER met2 ;
      RECT 503.630 402.140 503.770 402.560 ;
    END
  END r0_rd_out[99]
  PIN r0_rd_out[100]
    DIRECTION OUTPUT ;
    USE SIGNAL ;
    SHAPE ABUTMENT ;
    PORT
      LAYER met2 ;
      RECT 508.690 402.140 508.830 402.560 ;
    END
  END r0_rd_out[100]
  PIN r0_rd_out[101]
    DIRECTION OUTPUT ;
    USE SIGNAL ;
    SHAPE ABUTMENT ;
    PORT
      LAYER met2 ;
      RECT 513.750 402.140 513.890 402.560 ;
    END
  END r0_rd_out[101]
  PIN r0_rd_out[102]
    DIRECTION OUTPUT ;
    USE SIGNAL ;
    SHAPE ABUTMENT ;
    PORT
      LAYER met2 ;
      RECT 518.810 402.140 518.950 402.560 ;
    END
  END r0_rd_out[102]
  PIN r0_rd_out[103]
    DIRECTION OUTPUT ;
    USE SIGNAL ;
    SHAPE ABUTMENT ;
    PORT
      LAYER met2 ;
      RECT 523.870 402.140 524.010 402.560 ;
    END
  END r0_rd_out[103]
  PIN r0_rd_out[104]
    DIRECTION OUTPUT ;
    USE SIGNAL ;
    SHAPE ABUTMENT ;
    PORT
      LAYER met2 ;
      RECT 528.930 402.140 529.070 402.560 ;
    END
  END r0_rd_out[104]
  PIN r0_rd_out[105]
    DIRECTION OUTPUT ;
    USE SIGNAL ;
    SHAPE ABUTMENT ;
    PORT
      LAYER met2 ;
      RECT 533.990 402.140 534.130 402.560 ;
    END
  END r0_rd_out[105]
  PIN r0_rd_out[106]
    DIRECTION OUTPUT ;
    USE SIGNAL ;
    SHAPE ABUTMENT ;
    PORT
      LAYER met2 ;
      RECT 539.050 402.140 539.190 402.560 ;
    END
  END r0_rd_out[106]
  PIN r0_rd_out[107]
    DIRECTION OUTPUT ;
    USE SIGNAL ;
    SHAPE ABUTMENT ;
    PORT
      LAYER met2 ;
      RECT 544.110 402.140 544.250 402.560 ;
    END
  END r0_rd_out[107]
  PIN r0_rd_out[108]
    DIRECTION OUTPUT ;
    USE SIGNAL ;
    SHAPE ABUTMENT ;
    PORT
      LAYER met2 ;
      RECT 549.170 402.140 549.310 402.560 ;
    END
  END r0_rd_out[108]
  PIN r0_rd_out[109]
    DIRECTION OUTPUT ;
    USE SIGNAL ;
    SHAPE ABUTMENT ;
    PORT
      LAYER met2 ;
      RECT 554.230 402.140 554.370 402.560 ;
    END
  END r0_rd_out[109]
  PIN r0_rd_out[110]
    DIRECTION OUTPUT ;
    USE SIGNAL ;
    SHAPE ABUTMENT ;
    PORT
      LAYER met2 ;
      RECT 559.290 402.140 559.430 402.560 ;
    END
  END r0_rd_out[110]
  PIN r0_rd_out[111]
    DIRECTION OUTPUT ;
    USE SIGNAL ;
    SHAPE ABUTMENT ;
    PORT
      LAYER met2 ;
      RECT 564.350 402.140 564.490 402.560 ;
    END
  END r0_rd_out[111]
  PIN r0_rd_out[112]
    DIRECTION OUTPUT ;
    USE SIGNAL ;
    SHAPE ABUTMENT ;
    PORT
      LAYER met2 ;
      RECT 569.410 402.140 569.550 402.560 ;
    END
  END r0_rd_out[112]
  PIN r0_rd_out[113]
    DIRECTION OUTPUT ;
    USE SIGNAL ;
    SHAPE ABUTMENT ;
    PORT
      LAYER met2 ;
      RECT 574.470 402.140 574.610 402.560 ;
    END
  END r0_rd_out[113]
  PIN r0_rd_out[114]
    DIRECTION OUTPUT ;
    USE SIGNAL ;
    SHAPE ABUTMENT ;
    PORT
      LAYER met2 ;
      RECT 579.530 402.140 579.670 402.560 ;
    END
  END r0_rd_out[114]
  PIN r0_rd_out[115]
    DIRECTION OUTPUT ;
    USE SIGNAL ;
    SHAPE ABUTMENT ;
    PORT
      LAYER met2 ;
      RECT 584.590 402.140 584.730 402.560 ;
    END
  END r0_rd_out[115]
  PIN r0_rd_out[116]
    DIRECTION OUTPUT ;
    USE SIGNAL ;
    SHAPE ABUTMENT ;
    PORT
      LAYER met2 ;
      RECT 589.650 402.140 589.790 402.560 ;
    END
  END r0_rd_out[116]
  PIN r0_rd_out[117]
    DIRECTION OUTPUT ;
    USE SIGNAL ;
    SHAPE ABUTMENT ;
    PORT
      LAYER met2 ;
      RECT 594.710 402.140 594.850 402.560 ;
    END
  END r0_rd_out[117]
  PIN r0_rd_out[118]
    DIRECTION OUTPUT ;
    USE SIGNAL ;
    SHAPE ABUTMENT ;
    PORT
      LAYER met2 ;
      RECT 599.770 402.140 599.910 402.560 ;
    END
  END r0_rd_out[118]
  PIN r0_rd_out[119]
    DIRECTION OUTPUT ;
    USE SIGNAL ;
    SHAPE ABUTMENT ;
    PORT
      LAYER met2 ;
      RECT 604.830 402.140 604.970 402.560 ;
    END
  END r0_rd_out[119]
  PIN r0_rd_out[120]
    DIRECTION OUTPUT ;
    USE SIGNAL ;
    SHAPE ABUTMENT ;
    PORT
      LAYER met2 ;
      RECT 609.890 402.140 610.030 402.560 ;
    END
  END r0_rd_out[120]
  PIN r0_rd_out[121]
    DIRECTION OUTPUT ;
    USE SIGNAL ;
    SHAPE ABUTMENT ;
    PORT
      LAYER met2 ;
      RECT 614.950 402.140 615.090 402.560 ;
    END
  END r0_rd_out[121]
  PIN r0_rd_out[122]
    DIRECTION OUTPUT ;
    USE SIGNAL ;
    SHAPE ABUTMENT ;
    PORT
      LAYER met2 ;
      RECT 620.010 402.140 620.150 402.560 ;
    END
  END r0_rd_out[122]
  PIN r0_rd_out[123]
    DIRECTION OUTPUT ;
    USE SIGNAL ;
    SHAPE ABUTMENT ;
    PORT
      LAYER met2 ;
      RECT 625.070 402.140 625.210 402.560 ;
    END
  END r0_rd_out[123]
  PIN r0_rd_out[124]
    DIRECTION OUTPUT ;
    USE SIGNAL ;
    SHAPE ABUTMENT ;
    PORT
      LAYER met2 ;
      RECT 630.130 402.140 630.270 402.560 ;
    END
  END r0_rd_out[124]
  PIN r0_rd_out[125]
    DIRECTION OUTPUT ;
    USE SIGNAL ;
    SHAPE ABUTMENT ;
    PORT
      LAYER met2 ;
      RECT 635.190 402.140 635.330 402.560 ;
    END
  END r0_rd_out[125]
  PIN r0_rd_out[126]
    DIRECTION OUTPUT ;
    USE SIGNAL ;
    SHAPE ABUTMENT ;
    PORT
      LAYER met2 ;
      RECT 640.250 402.140 640.390 402.560 ;
    END
  END r0_rd_out[126]
  PIN r0_rd_out[127]
    DIRECTION OUTPUT ;
    USE SIGNAL ;
    SHAPE ABUTMENT ;
    PORT
      LAYER met2 ;
      RECT 645.310 402.140 645.450 402.560 ;
    END
  END r0_rd_out[127]
  PIN r0_rd_out[128]
    DIRECTION OUTPUT ;
    USE SIGNAL ;
    SHAPE ABUTMENT ;
    PORT
      LAYER met2 ;
      RECT 650.370 402.140 650.510 402.560 ;
    END
  END r0_rd_out[128]
  PIN r0_rd_out[129]
    DIRECTION OUTPUT ;
    USE SIGNAL ;
    SHAPE ABUTMENT ;
    PORT
      LAYER met2 ;
      RECT 655.430 402.140 655.570 402.560 ;
    END
  END r0_rd_out[129]
  PIN rw0_addr_in[0]
    DIRECTION INPUT ;
    USE SIGNAL ;
    SHAPE ABUTMENT ;
    PORT
      LAYER met3 ;
      RECT 0.000 318.090 0.900 318.390 ;
    END
  END rw0_addr_in[0]
  PIN rw0_addr_in[1]
    DIRECTION INPUT ;
    USE SIGNAL ;
    SHAPE ABUTMENT ;
    PORT
      LAYER met3 ;
      RECT 0.000 327.610 0.900 327.910 ;
    END
  END rw0_addr_in[1]
  PIN rw0_addr_in[2]
    DIRECTION INPUT ;
    USE SIGNAL ;
    SHAPE ABUTMENT ;
    PORT
      LAYER met3 ;
      RECT 0.000 337.130 0.900 337.430 ;
    END
  END rw0_addr_in[2]
  PIN rw0_addr_in[3]
    DIRECTION INPUT ;
    USE SIGNAL ;
    SHAPE ABUTMENT ;
    PORT
      LAYER met3 ;
      RECT 0.000 346.650 0.900 346.950 ;
    END
  END rw0_addr_in[3]
  PIN rw0_addr_in[4]
    DIRECTION INPUT ;
    USE SIGNAL ;
    SHAPE ABUTMENT ;
    PORT
      LAYER met3 ;
      RECT 705.200 308.570 706.100 308.870 ;
    END
  END rw0_addr_in[4]
  PIN rw0_addr_in[5]
    DIRECTION INPUT ;
    USE SIGNAL ;
    SHAPE ABUTMENT ;
    PORT
      LAYER met3 ;
      RECT 705.200 318.090 706.100 318.390 ;
    END
  END rw0_addr_in[5]
  PIN rw0_addr_in[6]
    DIRECTION INPUT ;
    USE SIGNAL ;
    SHAPE ABUTMENT ;
    PORT
      LAYER met3 ;
      RECT 705.200 327.610 706.100 327.910 ;
    END
  END rw0_addr_in[6]
  PIN r0_addr_in[0]
    DIRECTION INPUT ;
    USE SIGNAL ;
    SHAPE ABUTMENT ;
    PORT
      LAYER met3 ;
      RECT 0.000 356.170 0.900 356.470 ;
    END
  END r0_addr_in[0]
  PIN r0_addr_in[1]
    DIRECTION INPUT ;
    USE SIGNAL ;
    SHAPE ABUTMENT ;
    PORT
      LAYER met3 ;
      RECT 0.000 365.690 0.900 365.990 ;
    END
  END r0_addr_in[1]
  PIN r0_addr_in[2]
    DIRECTION INPUT ;
    USE SIGNAL ;
    SHAPE ABUTMENT ;
    PORT
      LAYER met3 ;
      RECT 0.000 375.210 0.900 375.510 ;
    END
  END r0_addr_in[2]
  PIN r0_addr_in[3]
    DIRECTION INPUT ;
    USE SIGNAL ;
    SHAPE ABUTMENT ;
    PORT
      LAYER met3 ;
      RECT 0.000 384.730 0.900 385.030 ;
    END
  END r0_addr_in[3]
  PIN r0_addr_in[4]
    DIRECTION INPUT ;
    USE SIGNAL ;
    SHAPE ABUTMENT ;
    PORT
      LAYER met3 ;
      RECT 705.200 337.130 706.100 337.430 ;
    END
  END r0_addr_in[4]
  PIN r0_addr_in[5]
    DIRECTION INPUT ;
    USE SIGNAL ;
    SHAPE ABUTMENT ;
    PORT
      LAYER met3 ;
      RECT 705.200 346.650 706.100 346.950 ;
    END
  END r0_addr_in[5]
  PIN r0_addr_in[6]
    DIRECTION INPUT ;
    USE SIGNAL ;
    SHAPE ABUTMENT ;
    PORT
      LAYER met3 ;
      RECT 705.200 356.170 706.100 356.470 ;
    END
  END r0_addr_in[6]
  PIN rw0_we_in
    DIRECTION INPUT ;
    USE SIGNAL ;
    SHAPE ABUTMENT ;
    PORT
      LAYER met2 ;
      RECT 660.490 402.140 660.630 402.560 ;
    END
  END rw0_we_in
  PIN rw0_ce_in
    DIRECTION INPUT ;
    USE SIGNAL ;
    SHAPE ABUTMENT ;
    PORT
      LAYER met2 ;
      RECT 665.550 402.140 665.690 402.560 ;
    END
  END rw0_ce_in
  PIN rw0_clk
    DIRECTION INPUT ;
    USE SIGNAL ;
    SHAPE ABUTMENT ;
    PORT
      LAYER met2 ;
      RECT 670.610 402.140 670.750 402.560 ;
    END
  END rw0_clk
  PIN r0_ce_in
    DIRECTION INPUT ;
    USE SIGNAL ;
    SHAPE ABUTMENT ;
    PORT
      LAYER met2 ;
      RECT 675.670 402.140 675.810 402.560 ;
    END
  END r0_ce_in
  PIN r0_clk
    DIRECTION INPUT ;
    USE SIGNAL ;
    SHAPE ABUTMENT ;
    PORT
      LAYER met2 ;
      RECT 680.730 402.140 680.870 402.560 ;
    END
  END r0_clk
  PIN VSS
    DIRECTION INOUT ;
    USE GROUND ;
    PORT
      LAYER met4 ;
      RECT 2.160 4.080 3.360 398.480 ;
      RECT 13.040 4.080 14.240 398.480 ;
      RECT 23.920 4.080 25.120 398.480 ;
      RECT 34.800 4.080 36.000 398.480 ;
      RECT 45.680 4.080 46.880 398.480 ;
      RECT 56.560 4.080 57.760 398.480 ;
      RECT 67.440 4.080 68.640 398.480 ;
      RECT 78.320 4.080 79.520 398.480 ;
      RECT 89.200 4.080 90.400 398.480 ;
      RECT 100.080 4.080 101.280 398.480 ;
      RECT 110.960 4.080 112.160 398.480 ;
      RECT 121.840 4.080 123.040 398.480 ;
      RECT 132.720 4.080 133.920 398.480 ;
      RECT 143.600 4.080 144.800 398.480 ;
      RECT 154.480 4.080 155.680 398.480 ;
      RECT 165.360 4.080 166.560 398.480 ;
      RECT 176.240 4.080 177.440 398.480 ;
      RECT 187.120 4.080 188.320 398.480 ;
      RECT 198.000 4.080 199.200 398.480 ;
      RECT 208.880 4.080 210.080 398.480 ;
      RECT 219.760 4.080 220.960 398.480 ;
      RECT 230.640 4.080 231.840 398.480 ;
      RECT 241.520 4.080 242.720 398.480 ;
      RECT 252.400 4.080 253.600 398.480 ;
      RECT 263.280 4.080 264.480 398.480 ;
      RECT 274.160 4.080 275.360 398.480 ;
      RECT 285.040 4.080 286.240 398.480 ;
      RECT 295.920 4.080 297.120 398.480 ;
      RECT 306.800 4.080 308.000 398.480 ;
      RECT 317.680 4.080 318.880 398.480 ;
      RECT 328.560 4.080 329.760 398.480 ;
      RECT 339.440 4.080 340.640 398.480 ;
      RECT 350.320 4.080 351.520 398.480 ;
      RECT 361.200 4.080 362.400 398.480 ;
      RECT 372.080 4.080 373.280 398.480 ;
      RECT 382.960 4.080 384.160 398.480 ;
      RECT 393.840 4.080 395.040 398.480 ;
      RECT 404.720 4.080 405.920 398.480 ;
      RECT 415.600 4.080 416.800 398.480 ;
      RECT 426.480 4.080 427.680 398.480 ;
      RECT 437.360 4.080 438.560 398.480 ;
      RECT 448.240 4.080 449.440 398.480 ;
      RECT 459.120 4.080 460.320 398.480 ;
      RECT 470.000 4.080 471.200 398.480 ;
      RECT 480.880 4.080 482.080 398.480 ;
      RECT 491.760 4.080 492.960 398.480 ;
      RECT 502.640 4.080 503.840 398.480 ;
      RECT 513.520 4.080 514.720 398.480 ;
      RECT 524.400 4.080 525.600 398.480 ;
      RECT 535.280 4.080 536.480 398.480 ;
      RECT 546.160 4.080 547.360 398.480 ;
      RECT 557.040 4.080 558.240 398.480 ;
      RECT 567.920 4.080 569.120 398.480 ;
      RECT 578.800 4.080 580.000 398.480 ;
      RECT 589.680 4.080 590.880 398.480 ;
      RECT 600.560 4.080 601.760 398.480 ;
      RECT 611.440 4.080 612.640 398.480 ;
      RECT 622.320 4.080 623.520 398.480 ;
      RECT 633.200 4.080 634.400 398.480 ;
      RECT 644.080 4.080 645.280 398.480 ;
      RECT 654.960 4.080 656.160 398.480 ;
      RECT 665.840 4.080 667.040 398.480 ;
      RECT 676.720 4.080 677.920 398.480 ;
      RECT 687.600 4.080 688.800 398.480 ;
      RECT 698.480 4.080 699.680 398.480 ;
    END
  END VSS
  PIN VDD
    DIRECTION INOUT ;
    USE POWER ;
    PORT
      LAYER met4 ;
      RECT 2.160 4.080 3.360 398.480 ;
      RECT 13.040 4.080 14.240 398.480 ;
      RECT 23.920 4.080 25.120 398.480 ;
      RECT 34.800 4.080 36.000 398.480 ;
      RECT 45.680 4.080 46.880 398.480 ;
      RECT 56.560 4.080 57.760 398.480 ;
      RECT 67.440 4.080 68.640 398.480 ;
      RECT 78.320 4.080 79.520 398.480 ;
      RECT 89.200 4.080 90.400 398.480 ;
      RECT 100.080 4.080 101.280 398.480 ;
      RECT 110.960 4.080 112.160 398.480 ;
      RECT 121.840 4.080 123.040 398.480 ;
      RECT 132.720 4.080 133.920 398.480 ;
      RECT 143.600 4.080 144.800 398.480 ;
      RECT 154.480 4.080 155.680 398.480 ;
      RECT 165.360 4.080 166.560 398.480 ;
      RECT 176.240 4.080 177.440 398.480 ;
      RECT 187.120 4.080 188.320 398.480 ;
      RECT 198.000 4.080 199.200 398.480 ;
      RECT 208.880 4.080 210.080 398.480 ;
      RECT 219.760 4.080 220.960 398.480 ;
      RECT 230.640 4.080 231.840 398.480 ;
      RECT 241.520 4.080 242.720 398.480 ;
      RECT 252.400 4.080 253.600 398.480 ;
      RECT 263.280 4.080 264.480 398.480 ;
      RECT 274.160 4.080 275.360 398.480 ;
      RECT 285.040 4.080 286.240 398.480 ;
      RECT 295.920 4.080 297.120 398.480 ;
      RECT 306.800 4.080 308.000 398.480 ;
      RECT 317.680 4.080 318.880 398.480 ;
      RECT 328.560 4.080 329.760 398.480 ;
      RECT 339.440 4.080 340.640 398.480 ;
      RECT 350.320 4.080 351.520 398.480 ;
      RECT 361.200 4.080 362.400 398.480 ;
      RECT 372.080 4.080 373.280 398.480 ;
      RECT 382.960 4.080 384.160 398.480 ;
      RECT 393.840 4.080 395.040 398.480 ;
      RECT 404.720 4.080 405.920 398.480 ;
      RECT 415.600 4.080 416.800 398.480 ;
      RECT 426.480 4.080 427.680 398.480 ;
      RECT 437.360 4.080 438.560 398.480 ;
      RECT 448.240 4.080 449.440 398.480 ;
      RECT 459.120 4.080 460.320 398.480 ;
      RECT 470.000 4.080 471.200 398.480 ;
      RECT 480.880 4.080 482.080 398.480 ;
      RECT 491.760 4.080 492.960 398.480 ;
      RECT 502.640 4.080 503.840 398.480 ;
      RECT 513.520 4.080 514.720 398.480 ;
      RECT 524.400 4.080 525.600 398.480 ;
      RECT 535.280 4.080 536.480 398.480 ;
      RECT 546.160 4.080 547.360 398.480 ;
      RECT 557.040 4.080 558.240 398.480 ;
      RECT 567.920 4.080 569.120 398.480 ;
      RECT 578.800 4.080 580.000 398.480 ;
      RECT 589.680 4.080 590.880 398.480 ;
      RECT 600.560 4.080 601.760 398.480 ;
      RECT 611.440 4.080 612.640 398.480 ;
      RECT 622.320 4.080 623.520 398.480 ;
      RECT 633.200 4.080 634.400 398.480 ;
      RECT 644.080 4.080 645.280 398.480 ;
      RECT 654.960 4.080 656.160 398.480 ;
      RECT 665.840 4.080 667.040 398.480 ;
      RECT 676.720 4.080 677.920 398.480 ;
      RECT 687.600 4.080 688.800 398.480 ;
      RECT 698.480 4.080 699.680 398.480 ;
    END
  END VDD
  OBS
    LAYER met1 ;
    RECT 0 0 706.100 402.560 ;
    LAYER met2 ;
    RECT 0 0 706.100 402.560 ;
    LAYER met3 ;
    RECT 0 0 706.100 402.560 ;
    LAYER met4 ;
    RECT 0 0 706.100 402.560 ;
  END
END fakeram130_1rw1r_130w128d

END LIBRARY
